# Generated by FakeRAM 2.0
VERSION 5.7 ;
BUSBITCHARS "[]" ;
PROPERTYDEFINITIONS
  MACRO width INTEGER ;
  MACRO depth INTEGER ;
  MACRO banks INTEGER ;
END PROPERTYDEFINITIONS
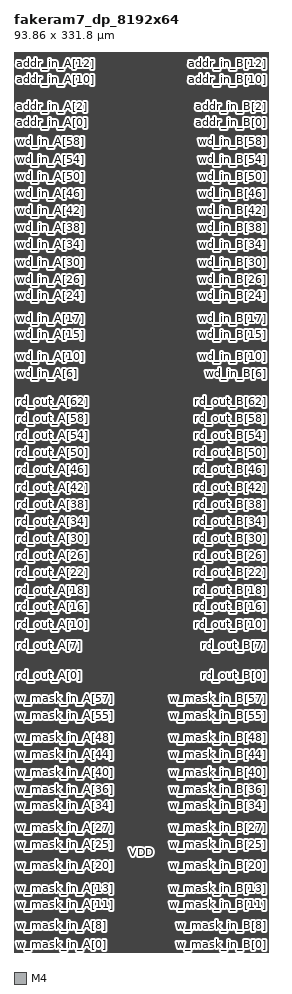
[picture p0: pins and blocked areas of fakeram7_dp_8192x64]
MACRO fakeram7_dp_8192x64
  PROPERTY width 64 ;
  PROPERTY depth 8192 ;
  PROPERTY banks 8 ;
  FOREIGN fakeram7_dp_8192x64 0 0 ;
  SYMMETRY X Y ;
  SIZE 93.860 BY 331.800 ;
  CLASS BLOCK ;
  PIN w_mask_in_A[0]
    DIRECTION INPUT ;
    USE SIGNAL ;
    SHAPE ABUTMENT ;
    PORT
      LAYER M4 ;
      RECT 0.000 0.048 0.024 0.072 ;
    END
  END w_mask_in_A[0]
  PIN w_mask_in_B[0]
    DIRECTION INPUT ;
    USE SIGNAL ;
    SHAPE ABUTMENT ;
    PORT
      LAYER M4 ;
      RECT 93.836 0.048 93.860 0.072 ;
    END
  END w_mask_in_B[0]
  PIN w_mask_in_A[1]
    DIRECTION INPUT ;
    USE SIGNAL ;
    SHAPE ABUTMENT ;
    PORT
      LAYER M4 ;
      RECT 0.000 1.632 0.024 1.656 ;
    END
  END w_mask_in_A[1]
  PIN w_mask_in_B[1]
    DIRECTION INPUT ;
    USE SIGNAL ;
    SHAPE ABUTMENT ;
    PORT
      LAYER M4 ;
      RECT 93.836 1.632 93.860 1.656 ;
    END
  END w_mask_in_B[1]
  PIN w_mask_in_A[2]
    DIRECTION INPUT ;
    USE SIGNAL ;
    SHAPE ABUTMENT ;
    PORT
      LAYER M4 ;
      RECT 0.000 3.216 0.024 3.240 ;
    END
  END w_mask_in_A[2]
  PIN w_mask_in_B[2]
    DIRECTION INPUT ;
    USE SIGNAL ;
    SHAPE ABUTMENT ;
    PORT
      LAYER M4 ;
      RECT 93.836 3.216 93.860 3.240 ;
    END
  END w_mask_in_B[2]
  PIN w_mask_in_A[3]
    DIRECTION INPUT ;
    USE SIGNAL ;
    SHAPE ABUTMENT ;
    PORT
      LAYER M4 ;
      RECT 0.000 4.800 0.024 4.824 ;
    END
  END w_mask_in_A[3]
  PIN w_mask_in_B[3]
    DIRECTION INPUT ;
    USE SIGNAL ;
    SHAPE ABUTMENT ;
    PORT
      LAYER M4 ;
      RECT 93.836 4.800 93.860 4.824 ;
    END
  END w_mask_in_B[3]
  PIN w_mask_in_A[4]
    DIRECTION INPUT ;
    USE SIGNAL ;
    SHAPE ABUTMENT ;
    PORT
      LAYER M4 ;
      RECT 0.000 6.384 0.024 6.408 ;
    END
  END w_mask_in_A[4]
  PIN w_mask_in_B[4]
    DIRECTION INPUT ;
    USE SIGNAL ;
    SHAPE ABUTMENT ;
    PORT
      LAYER M4 ;
      RECT 93.836 6.384 93.860 6.408 ;
    END
  END w_mask_in_B[4]
  PIN w_mask_in_A[5]
    DIRECTION INPUT ;
    USE SIGNAL ;
    SHAPE ABUTMENT ;
    PORT
      LAYER M4 ;
      RECT 0.000 7.968 0.024 7.992 ;
    END
  END w_mask_in_A[5]
  PIN w_mask_in_B[5]
    DIRECTION INPUT ;
    USE SIGNAL ;
    SHAPE ABUTMENT ;
    PORT
      LAYER M4 ;
      RECT 93.836 7.968 93.860 7.992 ;
    END
  END w_mask_in_B[5]
  PIN w_mask_in_A[6]
    DIRECTION INPUT ;
    USE SIGNAL ;
    SHAPE ABUTMENT ;
    PORT
      LAYER M4 ;
      RECT 0.000 9.552 0.024 9.576 ;
    END
  END w_mask_in_A[6]
  PIN w_mask_in_B[6]
    DIRECTION INPUT ;
    USE SIGNAL ;
    SHAPE ABUTMENT ;
    PORT
      LAYER M4 ;
      RECT 93.836 9.552 93.860 9.576 ;
    END
  END w_mask_in_B[6]
  PIN w_mask_in_A[7]
    DIRECTION INPUT ;
    USE SIGNAL ;
    SHAPE ABUTMENT ;
    PORT
      LAYER M4 ;
      RECT 0.000 11.136 0.024 11.160 ;
    END
  END w_mask_in_A[7]
  PIN w_mask_in_B[7]
    DIRECTION INPUT ;
    USE SIGNAL ;
    SHAPE ABUTMENT ;
    PORT
      LAYER M4 ;
      RECT 93.836 11.136 93.860 11.160 ;
    END
  END w_mask_in_B[7]
  PIN w_mask_in_A[8]
    DIRECTION INPUT ;
    USE SIGNAL ;
    SHAPE ABUTMENT ;
    PORT
      LAYER M4 ;
      RECT 0.000 12.720 0.024 12.744 ;
    END
  END w_mask_in_A[8]
  PIN w_mask_in_B[8]
    DIRECTION INPUT ;
    USE SIGNAL ;
    SHAPE ABUTMENT ;
    PORT
      LAYER M4 ;
      RECT 93.836 12.720 93.860 12.744 ;
    END
  END w_mask_in_B[8]
  PIN w_mask_in_A[9]
    DIRECTION INPUT ;
    USE SIGNAL ;
    SHAPE ABUTMENT ;
    PORT
      LAYER M4 ;
      RECT 0.000 14.304 0.024 14.328 ;
    END
  END w_mask_in_A[9]
  PIN w_mask_in_B[9]
    DIRECTION INPUT ;
    USE SIGNAL ;
    SHAPE ABUTMENT ;
    PORT
      LAYER M4 ;
      RECT 93.836 14.304 93.860 14.328 ;
    END
  END w_mask_in_B[9]
  PIN w_mask_in_A[10]
    DIRECTION INPUT ;
    USE SIGNAL ;
    SHAPE ABUTMENT ;
    PORT
      LAYER M4 ;
      RECT 0.000 15.888 0.024 15.912 ;
    END
  END w_mask_in_A[10]
  PIN w_mask_in_B[10]
    DIRECTION INPUT ;
    USE SIGNAL ;
    SHAPE ABUTMENT ;
    PORT
      LAYER M4 ;
      RECT 93.836 15.888 93.860 15.912 ;
    END
  END w_mask_in_B[10]
  PIN w_mask_in_A[11]
    DIRECTION INPUT ;
    USE SIGNAL ;
    SHAPE ABUTMENT ;
    PORT
      LAYER M4 ;
      RECT 0.000 17.472 0.024 17.496 ;
    END
  END w_mask_in_A[11]
  PIN w_mask_in_B[11]
    DIRECTION INPUT ;
    USE SIGNAL ;
    SHAPE ABUTMENT ;
    PORT
      LAYER M4 ;
      RECT 93.836 17.472 93.860 17.496 ;
    END
  END w_mask_in_B[11]
  PIN w_mask_in_A[12]
    DIRECTION INPUT ;
    USE SIGNAL ;
    SHAPE ABUTMENT ;
    PORT
      LAYER M4 ;
      RECT 0.000 19.056 0.024 19.080 ;
    END
  END w_mask_in_A[12]
  PIN w_mask_in_B[12]
    DIRECTION INPUT ;
    USE SIGNAL ;
    SHAPE ABUTMENT ;
    PORT
      LAYER M4 ;
      RECT 93.836 19.056 93.860 19.080 ;
    END
  END w_mask_in_B[12]
  PIN w_mask_in_A[13]
    DIRECTION INPUT ;
    USE SIGNAL ;
    SHAPE ABUTMENT ;
    PORT
      LAYER M4 ;
      RECT 0.000 20.640 0.024 20.664 ;
    END
  END w_mask_in_A[13]
  PIN w_mask_in_B[13]
    DIRECTION INPUT ;
    USE SIGNAL ;
    SHAPE ABUTMENT ;
    PORT
      LAYER M4 ;
      RECT 93.836 20.640 93.860 20.664 ;
    END
  END w_mask_in_B[13]
  PIN w_mask_in_A[14]
    DIRECTION INPUT ;
    USE SIGNAL ;
    SHAPE ABUTMENT ;
    PORT
      LAYER M4 ;
      RECT 0.000 22.224 0.024 22.248 ;
    END
  END w_mask_in_A[14]
  PIN w_mask_in_B[14]
    DIRECTION INPUT ;
    USE SIGNAL ;
    SHAPE ABUTMENT ;
    PORT
      LAYER M4 ;
      RECT 93.836 22.224 93.860 22.248 ;
    END
  END w_mask_in_B[14]
  PIN w_mask_in_A[15]
    DIRECTION INPUT ;
    USE SIGNAL ;
    SHAPE ABUTMENT ;
    PORT
      LAYER M4 ;
      RECT 0.000 23.808 0.024 23.832 ;
    END
  END w_mask_in_A[15]
  PIN w_mask_in_B[15]
    DIRECTION INPUT ;
    USE SIGNAL ;
    SHAPE ABUTMENT ;
    PORT
      LAYER M4 ;
      RECT 93.836 23.808 93.860 23.832 ;
    END
  END w_mask_in_B[15]
  PIN w_mask_in_A[16]
    DIRECTION INPUT ;
    USE SIGNAL ;
    SHAPE ABUTMENT ;
    PORT
      LAYER M4 ;
      RECT 0.000 25.392 0.024 25.416 ;
    END
  END w_mask_in_A[16]
  PIN w_mask_in_B[16]
    DIRECTION INPUT ;
    USE SIGNAL ;
    SHAPE ABUTMENT ;
    PORT
      LAYER M4 ;
      RECT 93.836 25.392 93.860 25.416 ;
    END
  END w_mask_in_B[16]
  PIN w_mask_in_A[17]
    DIRECTION INPUT ;
    USE SIGNAL ;
    SHAPE ABUTMENT ;
    PORT
      LAYER M4 ;
      RECT 0.000 26.976 0.024 27.000 ;
    END
  END w_mask_in_A[17]
  PIN w_mask_in_B[17]
    DIRECTION INPUT ;
    USE SIGNAL ;
    SHAPE ABUTMENT ;
    PORT
      LAYER M4 ;
      RECT 93.836 26.976 93.860 27.000 ;
    END
  END w_mask_in_B[17]
  PIN w_mask_in_A[18]
    DIRECTION INPUT ;
    USE SIGNAL ;
    SHAPE ABUTMENT ;
    PORT
      LAYER M4 ;
      RECT 0.000 28.560 0.024 28.584 ;
    END
  END w_mask_in_A[18]
  PIN w_mask_in_B[18]
    DIRECTION INPUT ;
    USE SIGNAL ;
    SHAPE ABUTMENT ;
    PORT
      LAYER M4 ;
      RECT 93.836 28.560 93.860 28.584 ;
    END
  END w_mask_in_B[18]
  PIN w_mask_in_A[19]
    DIRECTION INPUT ;
    USE SIGNAL ;
    SHAPE ABUTMENT ;
    PORT
      LAYER M4 ;
      RECT 0.000 30.144 0.024 30.168 ;
    END
  END w_mask_in_A[19]
  PIN w_mask_in_B[19]
    DIRECTION INPUT ;
    USE SIGNAL ;
    SHAPE ABUTMENT ;
    PORT
      LAYER M4 ;
      RECT 93.836 30.144 93.860 30.168 ;
    END
  END w_mask_in_B[19]
  PIN w_mask_in_A[20]
    DIRECTION INPUT ;
    USE SIGNAL ;
    SHAPE ABUTMENT ;
    PORT
      LAYER M4 ;
      RECT 0.000 31.728 0.024 31.752 ;
    END
  END w_mask_in_A[20]
  PIN w_mask_in_B[20]
    DIRECTION INPUT ;
    USE SIGNAL ;
    SHAPE ABUTMENT ;
    PORT
      LAYER M4 ;
      RECT 93.836 31.728 93.860 31.752 ;
    END
  END w_mask_in_B[20]
  PIN w_mask_in_A[21]
    DIRECTION INPUT ;
    USE SIGNAL ;
    SHAPE ABUTMENT ;
    PORT
      LAYER M4 ;
      RECT 0.000 33.312 0.024 33.336 ;
    END
  END w_mask_in_A[21]
  PIN w_mask_in_B[21]
    DIRECTION INPUT ;
    USE SIGNAL ;
    SHAPE ABUTMENT ;
    PORT
      LAYER M4 ;
      RECT 93.836 33.312 93.860 33.336 ;
    END
  END w_mask_in_B[21]
  PIN w_mask_in_A[22]
    DIRECTION INPUT ;
    USE SIGNAL ;
    SHAPE ABUTMENT ;
    PORT
      LAYER M4 ;
      RECT 0.000 34.896 0.024 34.920 ;
    END
  END w_mask_in_A[22]
  PIN w_mask_in_B[22]
    DIRECTION INPUT ;
    USE SIGNAL ;
    SHAPE ABUTMENT ;
    PORT
      LAYER M4 ;
      RECT 93.836 34.896 93.860 34.920 ;
    END
  END w_mask_in_B[22]
  PIN w_mask_in_A[23]
    DIRECTION INPUT ;
    USE SIGNAL ;
    SHAPE ABUTMENT ;
    PORT
      LAYER M4 ;
      RECT 0.000 36.480 0.024 36.504 ;
    END
  END w_mask_in_A[23]
  PIN w_mask_in_B[23]
    DIRECTION INPUT ;
    USE SIGNAL ;
    SHAPE ABUTMENT ;
    PORT
      LAYER M4 ;
      RECT 93.836 36.480 93.860 36.504 ;
    END
  END w_mask_in_B[23]
  PIN w_mask_in_A[24]
    DIRECTION INPUT ;
    USE SIGNAL ;
    SHAPE ABUTMENT ;
    PORT
      LAYER M4 ;
      RECT 0.000 38.064 0.024 38.088 ;
    END
  END w_mask_in_A[24]
  PIN w_mask_in_B[24]
    DIRECTION INPUT ;
    USE SIGNAL ;
    SHAPE ABUTMENT ;
    PORT
      LAYER M4 ;
      RECT 93.836 38.064 93.860 38.088 ;
    END
  END w_mask_in_B[24]
  PIN w_mask_in_A[25]
    DIRECTION INPUT ;
    USE SIGNAL ;
    SHAPE ABUTMENT ;
    PORT
      LAYER M4 ;
      RECT 0.000 39.648 0.024 39.672 ;
    END
  END w_mask_in_A[25]
  PIN w_mask_in_B[25]
    DIRECTION INPUT ;
    USE SIGNAL ;
    SHAPE ABUTMENT ;
    PORT
      LAYER M4 ;
      RECT 93.836 39.648 93.860 39.672 ;
    END
  END w_mask_in_B[25]
  PIN w_mask_in_A[26]
    DIRECTION INPUT ;
    USE SIGNAL ;
    SHAPE ABUTMENT ;
    PORT
      LAYER M4 ;
      RECT 0.000 41.232 0.024 41.256 ;
    END
  END w_mask_in_A[26]
  PIN w_mask_in_B[26]
    DIRECTION INPUT ;
    USE SIGNAL ;
    SHAPE ABUTMENT ;
    PORT
      LAYER M4 ;
      RECT 93.836 41.232 93.860 41.256 ;
    END
  END w_mask_in_B[26]
  PIN w_mask_in_A[27]
    DIRECTION INPUT ;
    USE SIGNAL ;
    SHAPE ABUTMENT ;
    PORT
      LAYER M4 ;
      RECT 0.000 42.816 0.024 42.840 ;
    END
  END w_mask_in_A[27]
  PIN w_mask_in_B[27]
    DIRECTION INPUT ;
    USE SIGNAL ;
    SHAPE ABUTMENT ;
    PORT
      LAYER M4 ;
      RECT 93.836 42.816 93.860 42.840 ;
    END
  END w_mask_in_B[27]
  PIN w_mask_in_A[28]
    DIRECTION INPUT ;
    USE SIGNAL ;
    SHAPE ABUTMENT ;
    PORT
      LAYER M4 ;
      RECT 0.000 44.400 0.024 44.424 ;
    END
  END w_mask_in_A[28]
  PIN w_mask_in_B[28]
    DIRECTION INPUT ;
    USE SIGNAL ;
    SHAPE ABUTMENT ;
    PORT
      LAYER M4 ;
      RECT 93.836 44.400 93.860 44.424 ;
    END
  END w_mask_in_B[28]
  PIN w_mask_in_A[29]
    DIRECTION INPUT ;
    USE SIGNAL ;
    SHAPE ABUTMENT ;
    PORT
      LAYER M4 ;
      RECT 0.000 45.984 0.024 46.008 ;
    END
  END w_mask_in_A[29]
  PIN w_mask_in_B[29]
    DIRECTION INPUT ;
    USE SIGNAL ;
    SHAPE ABUTMENT ;
    PORT
      LAYER M4 ;
      RECT 93.836 45.984 93.860 46.008 ;
    END
  END w_mask_in_B[29]
  PIN w_mask_in_A[30]
    DIRECTION INPUT ;
    USE SIGNAL ;
    SHAPE ABUTMENT ;
    PORT
      LAYER M4 ;
      RECT 0.000 47.568 0.024 47.592 ;
    END
  END w_mask_in_A[30]
  PIN w_mask_in_B[30]
    DIRECTION INPUT ;
    USE SIGNAL ;
    SHAPE ABUTMENT ;
    PORT
      LAYER M4 ;
      RECT 93.836 47.568 93.860 47.592 ;
    END
  END w_mask_in_B[30]
  PIN w_mask_in_A[31]
    DIRECTION INPUT ;
    USE SIGNAL ;
    SHAPE ABUTMENT ;
    PORT
      LAYER M4 ;
      RECT 0.000 49.152 0.024 49.176 ;
    END
  END w_mask_in_A[31]
  PIN w_mask_in_B[31]
    DIRECTION INPUT ;
    USE SIGNAL ;
    SHAPE ABUTMENT ;
    PORT
      LAYER M4 ;
      RECT 93.836 49.152 93.860 49.176 ;
    END
  END w_mask_in_B[31]
  PIN w_mask_in_A[32]
    DIRECTION INPUT ;
    USE SIGNAL ;
    SHAPE ABUTMENT ;
    PORT
      LAYER M4 ;
      RECT 0.000 50.736 0.024 50.760 ;
    END
  END w_mask_in_A[32]
  PIN w_mask_in_B[32]
    DIRECTION INPUT ;
    USE SIGNAL ;
    SHAPE ABUTMENT ;
    PORT
      LAYER M4 ;
      RECT 93.836 50.736 93.860 50.760 ;
    END
  END w_mask_in_B[32]
  PIN w_mask_in_A[33]
    DIRECTION INPUT ;
    USE SIGNAL ;
    SHAPE ABUTMENT ;
    PORT
      LAYER M4 ;
      RECT 0.000 52.320 0.024 52.344 ;
    END
  END w_mask_in_A[33]
  PIN w_mask_in_B[33]
    DIRECTION INPUT ;
    USE SIGNAL ;
    SHAPE ABUTMENT ;
    PORT
      LAYER M4 ;
      RECT 93.836 52.320 93.860 52.344 ;
    END
  END w_mask_in_B[33]
  PIN w_mask_in_A[34]
    DIRECTION INPUT ;
    USE SIGNAL ;
    SHAPE ABUTMENT ;
    PORT
      LAYER M4 ;
      RECT 0.000 53.904 0.024 53.928 ;
    END
  END w_mask_in_A[34]
  PIN w_mask_in_B[34]
    DIRECTION INPUT ;
    USE SIGNAL ;
    SHAPE ABUTMENT ;
    PORT
      LAYER M4 ;
      RECT 93.836 53.904 93.860 53.928 ;
    END
  END w_mask_in_B[34]
  PIN w_mask_in_A[35]
    DIRECTION INPUT ;
    USE SIGNAL ;
    SHAPE ABUTMENT ;
    PORT
      LAYER M4 ;
      RECT 0.000 55.488 0.024 55.512 ;
    END
  END w_mask_in_A[35]
  PIN w_mask_in_B[35]
    DIRECTION INPUT ;
    USE SIGNAL ;
    SHAPE ABUTMENT ;
    PORT
      LAYER M4 ;
      RECT 93.836 55.488 93.860 55.512 ;
    END
  END w_mask_in_B[35]
  PIN w_mask_in_A[36]
    DIRECTION INPUT ;
    USE SIGNAL ;
    SHAPE ABUTMENT ;
    PORT
      LAYER M4 ;
      RECT 0.000 57.072 0.024 57.096 ;
    END
  END w_mask_in_A[36]
  PIN w_mask_in_B[36]
    DIRECTION INPUT ;
    USE SIGNAL ;
    SHAPE ABUTMENT ;
    PORT
      LAYER M4 ;
      RECT 93.836 57.072 93.860 57.096 ;
    END
  END w_mask_in_B[36]
  PIN w_mask_in_A[37]
    DIRECTION INPUT ;
    USE SIGNAL ;
    SHAPE ABUTMENT ;
    PORT
      LAYER M4 ;
      RECT 0.000 58.656 0.024 58.680 ;
    END
  END w_mask_in_A[37]
  PIN w_mask_in_B[37]
    DIRECTION INPUT ;
    USE SIGNAL ;
    SHAPE ABUTMENT ;
    PORT
      LAYER M4 ;
      RECT 93.836 58.656 93.860 58.680 ;
    END
  END w_mask_in_B[37]
  PIN w_mask_in_A[38]
    DIRECTION INPUT ;
    USE SIGNAL ;
    SHAPE ABUTMENT ;
    PORT
      LAYER M4 ;
      RECT 0.000 60.240 0.024 60.264 ;
    END
  END w_mask_in_A[38]
  PIN w_mask_in_B[38]
    DIRECTION INPUT ;
    USE SIGNAL ;
    SHAPE ABUTMENT ;
    PORT
      LAYER M4 ;
      RECT 93.836 60.240 93.860 60.264 ;
    END
  END w_mask_in_B[38]
  PIN w_mask_in_A[39]
    DIRECTION INPUT ;
    USE SIGNAL ;
    SHAPE ABUTMENT ;
    PORT
      LAYER M4 ;
      RECT 0.000 61.824 0.024 61.848 ;
    END
  END w_mask_in_A[39]
  PIN w_mask_in_B[39]
    DIRECTION INPUT ;
    USE SIGNAL ;
    SHAPE ABUTMENT ;
    PORT
      LAYER M4 ;
      RECT 93.836 61.824 93.860 61.848 ;
    END
  END w_mask_in_B[39]
  PIN w_mask_in_A[40]
    DIRECTION INPUT ;
    USE SIGNAL ;
    SHAPE ABUTMENT ;
    PORT
      LAYER M4 ;
      RECT 0.000 63.408 0.024 63.432 ;
    END
  END w_mask_in_A[40]
  PIN w_mask_in_B[40]
    DIRECTION INPUT ;
    USE SIGNAL ;
    SHAPE ABUTMENT ;
    PORT
      LAYER M4 ;
      RECT 93.836 63.408 93.860 63.432 ;
    END
  END w_mask_in_B[40]
  PIN w_mask_in_A[41]
    DIRECTION INPUT ;
    USE SIGNAL ;
    SHAPE ABUTMENT ;
    PORT
      LAYER M4 ;
      RECT 0.000 64.992 0.024 65.016 ;
    END
  END w_mask_in_A[41]
  PIN w_mask_in_B[41]
    DIRECTION INPUT ;
    USE SIGNAL ;
    SHAPE ABUTMENT ;
    PORT
      LAYER M4 ;
      RECT 93.836 64.992 93.860 65.016 ;
    END
  END w_mask_in_B[41]
  PIN w_mask_in_A[42]
    DIRECTION INPUT ;
    USE SIGNAL ;
    SHAPE ABUTMENT ;
    PORT
      LAYER M4 ;
      RECT 0.000 66.576 0.024 66.600 ;
    END
  END w_mask_in_A[42]
  PIN w_mask_in_B[42]
    DIRECTION INPUT ;
    USE SIGNAL ;
    SHAPE ABUTMENT ;
    PORT
      LAYER M4 ;
      RECT 93.836 66.576 93.860 66.600 ;
    END
  END w_mask_in_B[42]
  PIN w_mask_in_A[43]
    DIRECTION INPUT ;
    USE SIGNAL ;
    SHAPE ABUTMENT ;
    PORT
      LAYER M4 ;
      RECT 0.000 68.160 0.024 68.184 ;
    END
  END w_mask_in_A[43]
  PIN w_mask_in_B[43]
    DIRECTION INPUT ;
    USE SIGNAL ;
    SHAPE ABUTMENT ;
    PORT
      LAYER M4 ;
      RECT 93.836 68.160 93.860 68.184 ;
    END
  END w_mask_in_B[43]
  PIN w_mask_in_A[44]
    DIRECTION INPUT ;
    USE SIGNAL ;
    SHAPE ABUTMENT ;
    PORT
      LAYER M4 ;
      RECT 0.000 69.744 0.024 69.768 ;
    END
  END w_mask_in_A[44]
  PIN w_mask_in_B[44]
    DIRECTION INPUT ;
    USE SIGNAL ;
    SHAPE ABUTMENT ;
    PORT
      LAYER M4 ;
      RECT 93.836 69.744 93.860 69.768 ;
    END
  END w_mask_in_B[44]
  PIN w_mask_in_A[45]
    DIRECTION INPUT ;
    USE SIGNAL ;
    SHAPE ABUTMENT ;
    PORT
      LAYER M4 ;
      RECT 0.000 71.328 0.024 71.352 ;
    END
  END w_mask_in_A[45]
  PIN w_mask_in_B[45]
    DIRECTION INPUT ;
    USE SIGNAL ;
    SHAPE ABUTMENT ;
    PORT
      LAYER M4 ;
      RECT 93.836 71.328 93.860 71.352 ;
    END
  END w_mask_in_B[45]
  PIN w_mask_in_A[46]
    DIRECTION INPUT ;
    USE SIGNAL ;
    SHAPE ABUTMENT ;
    PORT
      LAYER M4 ;
      RECT 0.000 72.912 0.024 72.936 ;
    END
  END w_mask_in_A[46]
  PIN w_mask_in_B[46]
    DIRECTION INPUT ;
    USE SIGNAL ;
    SHAPE ABUTMENT ;
    PORT
      LAYER M4 ;
      RECT 93.836 72.912 93.860 72.936 ;
    END
  END w_mask_in_B[46]
  PIN w_mask_in_A[47]
    DIRECTION INPUT ;
    USE SIGNAL ;
    SHAPE ABUTMENT ;
    PORT
      LAYER M4 ;
      RECT 0.000 74.496 0.024 74.520 ;
    END
  END w_mask_in_A[47]
  PIN w_mask_in_B[47]
    DIRECTION INPUT ;
    USE SIGNAL ;
    SHAPE ABUTMENT ;
    PORT
      LAYER M4 ;
      RECT 93.836 74.496 93.860 74.520 ;
    END
  END w_mask_in_B[47]
  PIN w_mask_in_A[48]
    DIRECTION INPUT ;
    USE SIGNAL ;
    SHAPE ABUTMENT ;
    PORT
      LAYER M4 ;
      RECT 0.000 76.080 0.024 76.104 ;
    END
  END w_mask_in_A[48]
  PIN w_mask_in_B[48]
    DIRECTION INPUT ;
    USE SIGNAL ;
    SHAPE ABUTMENT ;
    PORT
      LAYER M4 ;
      RECT 93.836 76.080 93.860 76.104 ;
    END
  END w_mask_in_B[48]
  PIN w_mask_in_A[49]
    DIRECTION INPUT ;
    USE SIGNAL ;
    SHAPE ABUTMENT ;
    PORT
      LAYER M4 ;
      RECT 0.000 77.664 0.024 77.688 ;
    END
  END w_mask_in_A[49]
  PIN w_mask_in_B[49]
    DIRECTION INPUT ;
    USE SIGNAL ;
    SHAPE ABUTMENT ;
    PORT
      LAYER M4 ;
      RECT 93.836 77.664 93.860 77.688 ;
    END
  END w_mask_in_B[49]
  PIN w_mask_in_A[50]
    DIRECTION INPUT ;
    USE SIGNAL ;
    SHAPE ABUTMENT ;
    PORT
      LAYER M4 ;
      RECT 0.000 79.248 0.024 79.272 ;
    END
  END w_mask_in_A[50]
  PIN w_mask_in_B[50]
    DIRECTION INPUT ;
    USE SIGNAL ;
    SHAPE ABUTMENT ;
    PORT
      LAYER M4 ;
      RECT 93.836 79.248 93.860 79.272 ;
    END
  END w_mask_in_B[50]
  PIN w_mask_in_A[51]
    DIRECTION INPUT ;
    USE SIGNAL ;
    SHAPE ABUTMENT ;
    PORT
      LAYER M4 ;
      RECT 0.000 80.832 0.024 80.856 ;
    END
  END w_mask_in_A[51]
  PIN w_mask_in_B[51]
    DIRECTION INPUT ;
    USE SIGNAL ;
    SHAPE ABUTMENT ;
    PORT
      LAYER M4 ;
      RECT 93.836 80.832 93.860 80.856 ;
    END
  END w_mask_in_B[51]
  PIN w_mask_in_A[52]
    DIRECTION INPUT ;
    USE SIGNAL ;
    SHAPE ABUTMENT ;
    PORT
      LAYER M4 ;
      RECT 0.000 82.416 0.024 82.440 ;
    END
  END w_mask_in_A[52]
  PIN w_mask_in_B[52]
    DIRECTION INPUT ;
    USE SIGNAL ;
    SHAPE ABUTMENT ;
    PORT
      LAYER M4 ;
      RECT 93.836 82.416 93.860 82.440 ;
    END
  END w_mask_in_B[52]
  PIN w_mask_in_A[53]
    DIRECTION INPUT ;
    USE SIGNAL ;
    SHAPE ABUTMENT ;
    PORT
      LAYER M4 ;
      RECT 0.000 84.000 0.024 84.024 ;
    END
  END w_mask_in_A[53]
  PIN w_mask_in_B[53]
    DIRECTION INPUT ;
    USE SIGNAL ;
    SHAPE ABUTMENT ;
    PORT
      LAYER M4 ;
      RECT 93.836 84.000 93.860 84.024 ;
    END
  END w_mask_in_B[53]
  PIN w_mask_in_A[54]
    DIRECTION INPUT ;
    USE SIGNAL ;
    SHAPE ABUTMENT ;
    PORT
      LAYER M4 ;
      RECT 0.000 85.584 0.024 85.608 ;
    END
  END w_mask_in_A[54]
  PIN w_mask_in_B[54]
    DIRECTION INPUT ;
    USE SIGNAL ;
    SHAPE ABUTMENT ;
    PORT
      LAYER M4 ;
      RECT 93.836 85.584 93.860 85.608 ;
    END
  END w_mask_in_B[54]
  PIN w_mask_in_A[55]
    DIRECTION INPUT ;
    USE SIGNAL ;
    SHAPE ABUTMENT ;
    PORT
      LAYER M4 ;
      RECT 0.000 87.168 0.024 87.192 ;
    END
  END w_mask_in_A[55]
  PIN w_mask_in_B[55]
    DIRECTION INPUT ;
    USE SIGNAL ;
    SHAPE ABUTMENT ;
    PORT
      LAYER M4 ;
      RECT 93.836 87.168 93.860 87.192 ;
    END
  END w_mask_in_B[55]
  PIN w_mask_in_A[56]
    DIRECTION INPUT ;
    USE SIGNAL ;
    SHAPE ABUTMENT ;
    PORT
      LAYER M4 ;
      RECT 0.000 88.752 0.024 88.776 ;
    END
  END w_mask_in_A[56]
  PIN w_mask_in_B[56]
    DIRECTION INPUT ;
    USE SIGNAL ;
    SHAPE ABUTMENT ;
    PORT
      LAYER M4 ;
      RECT 93.836 88.752 93.860 88.776 ;
    END
  END w_mask_in_B[56]
  PIN w_mask_in_A[57]
    DIRECTION INPUT ;
    USE SIGNAL ;
    SHAPE ABUTMENT ;
    PORT
      LAYER M4 ;
      RECT 0.000 90.336 0.024 90.360 ;
    END
  END w_mask_in_A[57]
  PIN w_mask_in_B[57]
    DIRECTION INPUT ;
    USE SIGNAL ;
    SHAPE ABUTMENT ;
    PORT
      LAYER M4 ;
      RECT 93.836 90.336 93.860 90.360 ;
    END
  END w_mask_in_B[57]
  PIN w_mask_in_A[58]
    DIRECTION INPUT ;
    USE SIGNAL ;
    SHAPE ABUTMENT ;
    PORT
      LAYER M4 ;
      RECT 0.000 91.920 0.024 91.944 ;
    END
  END w_mask_in_A[58]
  PIN w_mask_in_B[58]
    DIRECTION INPUT ;
    USE SIGNAL ;
    SHAPE ABUTMENT ;
    PORT
      LAYER M4 ;
      RECT 93.836 91.920 93.860 91.944 ;
    END
  END w_mask_in_B[58]
  PIN w_mask_in_A[59]
    DIRECTION INPUT ;
    USE SIGNAL ;
    SHAPE ABUTMENT ;
    PORT
      LAYER M4 ;
      RECT 0.000 93.504 0.024 93.528 ;
    END
  END w_mask_in_A[59]
  PIN w_mask_in_B[59]
    DIRECTION INPUT ;
    USE SIGNAL ;
    SHAPE ABUTMENT ;
    PORT
      LAYER M4 ;
      RECT 93.836 93.504 93.860 93.528 ;
    END
  END w_mask_in_B[59]
  PIN w_mask_in_A[60]
    DIRECTION INPUT ;
    USE SIGNAL ;
    SHAPE ABUTMENT ;
    PORT
      LAYER M4 ;
      RECT 0.000 95.088 0.024 95.112 ;
    END
  END w_mask_in_A[60]
  PIN w_mask_in_B[60]
    DIRECTION INPUT ;
    USE SIGNAL ;
    SHAPE ABUTMENT ;
    PORT
      LAYER M4 ;
      RECT 93.836 95.088 93.860 95.112 ;
    END
  END w_mask_in_B[60]
  PIN w_mask_in_A[61]
    DIRECTION INPUT ;
    USE SIGNAL ;
    SHAPE ABUTMENT ;
    PORT
      LAYER M4 ;
      RECT 0.000 96.672 0.024 96.696 ;
    END
  END w_mask_in_A[61]
  PIN w_mask_in_B[61]
    DIRECTION INPUT ;
    USE SIGNAL ;
    SHAPE ABUTMENT ;
    PORT
      LAYER M4 ;
      RECT 93.836 96.672 93.860 96.696 ;
    END
  END w_mask_in_B[61]
  PIN w_mask_in_A[62]
    DIRECTION INPUT ;
    USE SIGNAL ;
    SHAPE ABUTMENT ;
    PORT
      LAYER M4 ;
      RECT 0.000 98.256 0.024 98.280 ;
    END
  END w_mask_in_A[62]
  PIN w_mask_in_B[62]
    DIRECTION INPUT ;
    USE SIGNAL ;
    SHAPE ABUTMENT ;
    PORT
      LAYER M4 ;
      RECT 93.836 98.256 93.860 98.280 ;
    END
  END w_mask_in_B[62]
  PIN w_mask_in_A[63]
    DIRECTION INPUT ;
    USE SIGNAL ;
    SHAPE ABUTMENT ;
    PORT
      LAYER M4 ;
      RECT 0.000 99.840 0.024 99.864 ;
    END
  END w_mask_in_A[63]
  PIN w_mask_in_B[63]
    DIRECTION INPUT ;
    USE SIGNAL ;
    SHAPE ABUTMENT ;
    PORT
      LAYER M4 ;
      RECT 93.836 99.840 93.860 99.864 ;
    END
  END w_mask_in_B[63]
  PIN rd_out_A[0]
    DIRECTION OUTPUT ;
    USE SIGNAL ;
    SHAPE ABUTMENT ;
    PORT
      LAYER M4 ;
      RECT 0.000 101.952 0.024 101.976 ;
    END
  END rd_out_A[0]
  PIN rd_out_B[0]
    DIRECTION OUTPUT ;
    USE SIGNAL ;
    SHAPE ABUTMENT ;
    PORT
      LAYER M4 ;
      RECT 93.836 101.952 93.860 101.976 ;
    END
  END rd_out_B[0]
  PIN rd_out_A[1]
    DIRECTION OUTPUT ;
    USE SIGNAL ;
    SHAPE ABUTMENT ;
    PORT
      LAYER M4 ;
      RECT 0.000 103.536 0.024 103.560 ;
    END
  END rd_out_A[1]
  PIN rd_out_B[1]
    DIRECTION OUTPUT ;
    USE SIGNAL ;
    SHAPE ABUTMENT ;
    PORT
      LAYER M4 ;
      RECT 93.836 103.536 93.860 103.560 ;
    END
  END rd_out_B[1]
  PIN rd_out_A[2]
    DIRECTION OUTPUT ;
    USE SIGNAL ;
    SHAPE ABUTMENT ;
    PORT
      LAYER M4 ;
      RECT 0.000 105.120 0.024 105.144 ;
    END
  END rd_out_A[2]
  PIN rd_out_B[2]
    DIRECTION OUTPUT ;
    USE SIGNAL ;
    SHAPE ABUTMENT ;
    PORT
      LAYER M4 ;
      RECT 93.836 105.120 93.860 105.144 ;
    END
  END rd_out_B[2]
  PIN rd_out_A[3]
    DIRECTION OUTPUT ;
    USE SIGNAL ;
    SHAPE ABUTMENT ;
    PORT
      LAYER M4 ;
      RECT 0.000 106.704 0.024 106.728 ;
    END
  END rd_out_A[3]
  PIN rd_out_B[3]
    DIRECTION OUTPUT ;
    USE SIGNAL ;
    SHAPE ABUTMENT ;
    PORT
      LAYER M4 ;
      RECT 93.836 106.704 93.860 106.728 ;
    END
  END rd_out_B[3]
  PIN rd_out_A[4]
    DIRECTION OUTPUT ;
    USE SIGNAL ;
    SHAPE ABUTMENT ;
    PORT
      LAYER M4 ;
      RECT 0.000 108.288 0.024 108.312 ;
    END
  END rd_out_A[4]
  PIN rd_out_B[4]
    DIRECTION OUTPUT ;
    USE SIGNAL ;
    SHAPE ABUTMENT ;
    PORT
      LAYER M4 ;
      RECT 93.836 108.288 93.860 108.312 ;
    END
  END rd_out_B[4]
  PIN rd_out_A[5]
    DIRECTION OUTPUT ;
    USE SIGNAL ;
    SHAPE ABUTMENT ;
    PORT
      LAYER M4 ;
      RECT 0.000 109.872 0.024 109.896 ;
    END
  END rd_out_A[5]
  PIN rd_out_B[5]
    DIRECTION OUTPUT ;
    USE SIGNAL ;
    SHAPE ABUTMENT ;
    PORT
      LAYER M4 ;
      RECT 93.836 109.872 93.860 109.896 ;
    END
  END rd_out_B[5]
  PIN rd_out_A[6]
    DIRECTION OUTPUT ;
    USE SIGNAL ;
    SHAPE ABUTMENT ;
    PORT
      LAYER M4 ;
      RECT 0.000 111.456 0.024 111.480 ;
    END
  END rd_out_A[6]
  PIN rd_out_B[6]
    DIRECTION OUTPUT ;
    USE SIGNAL ;
    SHAPE ABUTMENT ;
    PORT
      LAYER M4 ;
      RECT 93.836 111.456 93.860 111.480 ;
    END
  END rd_out_B[6]
  PIN rd_out_A[7]
    DIRECTION OUTPUT ;
    USE SIGNAL ;
    SHAPE ABUTMENT ;
    PORT
      LAYER M4 ;
      RECT 0.000 113.040 0.024 113.064 ;
    END
  END rd_out_A[7]
  PIN rd_out_B[7]
    DIRECTION OUTPUT ;
    USE SIGNAL ;
    SHAPE ABUTMENT ;
    PORT
      LAYER M4 ;
      RECT 93.836 113.040 93.860 113.064 ;
    END
  END rd_out_B[7]
  PIN rd_out_A[8]
    DIRECTION OUTPUT ;
    USE SIGNAL ;
    SHAPE ABUTMENT ;
    PORT
      LAYER M4 ;
      RECT 0.000 114.624 0.024 114.648 ;
    END
  END rd_out_A[8]
  PIN rd_out_B[8]
    DIRECTION OUTPUT ;
    USE SIGNAL ;
    SHAPE ABUTMENT ;
    PORT
      LAYER M4 ;
      RECT 93.836 114.624 93.860 114.648 ;
    END
  END rd_out_B[8]
  PIN rd_out_A[9]
    DIRECTION OUTPUT ;
    USE SIGNAL ;
    SHAPE ABUTMENT ;
    PORT
      LAYER M4 ;
      RECT 0.000 116.208 0.024 116.232 ;
    END
  END rd_out_A[9]
  PIN rd_out_B[9]
    DIRECTION OUTPUT ;
    USE SIGNAL ;
    SHAPE ABUTMENT ;
    PORT
      LAYER M4 ;
      RECT 93.836 116.208 93.860 116.232 ;
    END
  END rd_out_B[9]
  PIN rd_out_A[10]
    DIRECTION OUTPUT ;
    USE SIGNAL ;
    SHAPE ABUTMENT ;
    PORT
      LAYER M4 ;
      RECT 0.000 117.792 0.024 117.816 ;
    END
  END rd_out_A[10]
  PIN rd_out_B[10]
    DIRECTION OUTPUT ;
    USE SIGNAL ;
    SHAPE ABUTMENT ;
    PORT
      LAYER M4 ;
      RECT 93.836 117.792 93.860 117.816 ;
    END
  END rd_out_B[10]
  PIN rd_out_A[11]
    DIRECTION OUTPUT ;
    USE SIGNAL ;
    SHAPE ABUTMENT ;
    PORT
      LAYER M4 ;
      RECT 0.000 119.376 0.024 119.400 ;
    END
  END rd_out_A[11]
  PIN rd_out_B[11]
    DIRECTION OUTPUT ;
    USE SIGNAL ;
    SHAPE ABUTMENT ;
    PORT
      LAYER M4 ;
      RECT 93.836 119.376 93.860 119.400 ;
    END
  END rd_out_B[11]
  PIN rd_out_A[12]
    DIRECTION OUTPUT ;
    USE SIGNAL ;
    SHAPE ABUTMENT ;
    PORT
      LAYER M4 ;
      RECT 0.000 120.960 0.024 120.984 ;
    END
  END rd_out_A[12]
  PIN rd_out_B[12]
    DIRECTION OUTPUT ;
    USE SIGNAL ;
    SHAPE ABUTMENT ;
    PORT
      LAYER M4 ;
      RECT 93.836 120.960 93.860 120.984 ;
    END
  END rd_out_B[12]
  PIN rd_out_A[13]
    DIRECTION OUTPUT ;
    USE SIGNAL ;
    SHAPE ABUTMENT ;
    PORT
      LAYER M4 ;
      RECT 0.000 122.544 0.024 122.568 ;
    END
  END rd_out_A[13]
  PIN rd_out_B[13]
    DIRECTION OUTPUT ;
    USE SIGNAL ;
    SHAPE ABUTMENT ;
    PORT
      LAYER M4 ;
      RECT 93.836 122.544 93.860 122.568 ;
    END
  END rd_out_B[13]
  PIN rd_out_A[14]
    DIRECTION OUTPUT ;
    USE SIGNAL ;
    SHAPE ABUTMENT ;
    PORT
      LAYER M4 ;
      RECT 0.000 124.128 0.024 124.152 ;
    END
  END rd_out_A[14]
  PIN rd_out_B[14]
    DIRECTION OUTPUT ;
    USE SIGNAL ;
    SHAPE ABUTMENT ;
    PORT
      LAYER M4 ;
      RECT 93.836 124.128 93.860 124.152 ;
    END
  END rd_out_B[14]
  PIN rd_out_A[15]
    DIRECTION OUTPUT ;
    USE SIGNAL ;
    SHAPE ABUTMENT ;
    PORT
      LAYER M4 ;
      RECT 0.000 125.712 0.024 125.736 ;
    END
  END rd_out_A[15]
  PIN rd_out_B[15]
    DIRECTION OUTPUT ;
    USE SIGNAL ;
    SHAPE ABUTMENT ;
    PORT
      LAYER M4 ;
      RECT 93.836 125.712 93.860 125.736 ;
    END
  END rd_out_B[15]
  PIN rd_out_A[16]
    DIRECTION OUTPUT ;
    USE SIGNAL ;
    SHAPE ABUTMENT ;
    PORT
      LAYER M4 ;
      RECT 0.000 127.296 0.024 127.320 ;
    END
  END rd_out_A[16]
  PIN rd_out_B[16]
    DIRECTION OUTPUT ;
    USE SIGNAL ;
    SHAPE ABUTMENT ;
    PORT
      LAYER M4 ;
      RECT 93.836 127.296 93.860 127.320 ;
    END
  END rd_out_B[16]
  PIN rd_out_A[17]
    DIRECTION OUTPUT ;
    USE SIGNAL ;
    SHAPE ABUTMENT ;
    PORT
      LAYER M4 ;
      RECT 0.000 128.880 0.024 128.904 ;
    END
  END rd_out_A[17]
  PIN rd_out_B[17]
    DIRECTION OUTPUT ;
    USE SIGNAL ;
    SHAPE ABUTMENT ;
    PORT
      LAYER M4 ;
      RECT 93.836 128.880 93.860 128.904 ;
    END
  END rd_out_B[17]
  PIN rd_out_A[18]
    DIRECTION OUTPUT ;
    USE SIGNAL ;
    SHAPE ABUTMENT ;
    PORT
      LAYER M4 ;
      RECT 0.000 130.464 0.024 130.488 ;
    END
  END rd_out_A[18]
  PIN rd_out_B[18]
    DIRECTION OUTPUT ;
    USE SIGNAL ;
    SHAPE ABUTMENT ;
    PORT
      LAYER M4 ;
      RECT 93.836 130.464 93.860 130.488 ;
    END
  END rd_out_B[18]
  PIN rd_out_A[19]
    DIRECTION OUTPUT ;
    USE SIGNAL ;
    SHAPE ABUTMENT ;
    PORT
      LAYER M4 ;
      RECT 0.000 132.048 0.024 132.072 ;
    END
  END rd_out_A[19]
  PIN rd_out_B[19]
    DIRECTION OUTPUT ;
    USE SIGNAL ;
    SHAPE ABUTMENT ;
    PORT
      LAYER M4 ;
      RECT 93.836 132.048 93.860 132.072 ;
    END
  END rd_out_B[19]
  PIN rd_out_A[20]
    DIRECTION OUTPUT ;
    USE SIGNAL ;
    SHAPE ABUTMENT ;
    PORT
      LAYER M4 ;
      RECT 0.000 133.632 0.024 133.656 ;
    END
  END rd_out_A[20]
  PIN rd_out_B[20]
    DIRECTION OUTPUT ;
    USE SIGNAL ;
    SHAPE ABUTMENT ;
    PORT
      LAYER M4 ;
      RECT 93.836 133.632 93.860 133.656 ;
    END
  END rd_out_B[20]
  PIN rd_out_A[21]
    DIRECTION OUTPUT ;
    USE SIGNAL ;
    SHAPE ABUTMENT ;
    PORT
      LAYER M4 ;
      RECT 0.000 135.216 0.024 135.240 ;
    END
  END rd_out_A[21]
  PIN rd_out_B[21]
    DIRECTION OUTPUT ;
    USE SIGNAL ;
    SHAPE ABUTMENT ;
    PORT
      LAYER M4 ;
      RECT 93.836 135.216 93.860 135.240 ;
    END
  END rd_out_B[21]
  PIN rd_out_A[22]
    DIRECTION OUTPUT ;
    USE SIGNAL ;
    SHAPE ABUTMENT ;
    PORT
      LAYER M4 ;
      RECT 0.000 136.800 0.024 136.824 ;
    END
  END rd_out_A[22]
  PIN rd_out_B[22]
    DIRECTION OUTPUT ;
    USE SIGNAL ;
    SHAPE ABUTMENT ;
    PORT
      LAYER M4 ;
      RECT 93.836 136.800 93.860 136.824 ;
    END
  END rd_out_B[22]
  PIN rd_out_A[23]
    DIRECTION OUTPUT ;
    USE SIGNAL ;
    SHAPE ABUTMENT ;
    PORT
      LAYER M4 ;
      RECT 0.000 138.384 0.024 138.408 ;
    END
  END rd_out_A[23]
  PIN rd_out_B[23]
    DIRECTION OUTPUT ;
    USE SIGNAL ;
    SHAPE ABUTMENT ;
    PORT
      LAYER M4 ;
      RECT 93.836 138.384 93.860 138.408 ;
    END
  END rd_out_B[23]
  PIN rd_out_A[24]
    DIRECTION OUTPUT ;
    USE SIGNAL ;
    SHAPE ABUTMENT ;
    PORT
      LAYER M4 ;
      RECT 0.000 139.968 0.024 139.992 ;
    END
  END rd_out_A[24]
  PIN rd_out_B[24]
    DIRECTION OUTPUT ;
    USE SIGNAL ;
    SHAPE ABUTMENT ;
    PORT
      LAYER M4 ;
      RECT 93.836 139.968 93.860 139.992 ;
    END
  END rd_out_B[24]
  PIN rd_out_A[25]
    DIRECTION OUTPUT ;
    USE SIGNAL ;
    SHAPE ABUTMENT ;
    PORT
      LAYER M4 ;
      RECT 0.000 141.552 0.024 141.576 ;
    END
  END rd_out_A[25]
  PIN rd_out_B[25]
    DIRECTION OUTPUT ;
    USE SIGNAL ;
    SHAPE ABUTMENT ;
    PORT
      LAYER M4 ;
      RECT 93.836 141.552 93.860 141.576 ;
    END
  END rd_out_B[25]
  PIN rd_out_A[26]
    DIRECTION OUTPUT ;
    USE SIGNAL ;
    SHAPE ABUTMENT ;
    PORT
      LAYER M4 ;
      RECT 0.000 143.136 0.024 143.160 ;
    END
  END rd_out_A[26]
  PIN rd_out_B[26]
    DIRECTION OUTPUT ;
    USE SIGNAL ;
    SHAPE ABUTMENT ;
    PORT
      LAYER M4 ;
      RECT 93.836 143.136 93.860 143.160 ;
    END
  END rd_out_B[26]
  PIN rd_out_A[27]
    DIRECTION OUTPUT ;
    USE SIGNAL ;
    SHAPE ABUTMENT ;
    PORT
      LAYER M4 ;
      RECT 0.000 144.720 0.024 144.744 ;
    END
  END rd_out_A[27]
  PIN rd_out_B[27]
    DIRECTION OUTPUT ;
    USE SIGNAL ;
    SHAPE ABUTMENT ;
    PORT
      LAYER M4 ;
      RECT 93.836 144.720 93.860 144.744 ;
    END
  END rd_out_B[27]
  PIN rd_out_A[28]
    DIRECTION OUTPUT ;
    USE SIGNAL ;
    SHAPE ABUTMENT ;
    PORT
      LAYER M4 ;
      RECT 0.000 146.304 0.024 146.328 ;
    END
  END rd_out_A[28]
  PIN rd_out_B[28]
    DIRECTION OUTPUT ;
    USE SIGNAL ;
    SHAPE ABUTMENT ;
    PORT
      LAYER M4 ;
      RECT 93.836 146.304 93.860 146.328 ;
    END
  END rd_out_B[28]
  PIN rd_out_A[29]
    DIRECTION OUTPUT ;
    USE SIGNAL ;
    SHAPE ABUTMENT ;
    PORT
      LAYER M4 ;
      RECT 0.000 147.888 0.024 147.912 ;
    END
  END rd_out_A[29]
  PIN rd_out_B[29]
    DIRECTION OUTPUT ;
    USE SIGNAL ;
    SHAPE ABUTMENT ;
    PORT
      LAYER M4 ;
      RECT 93.836 147.888 93.860 147.912 ;
    END
  END rd_out_B[29]
  PIN rd_out_A[30]
    DIRECTION OUTPUT ;
    USE SIGNAL ;
    SHAPE ABUTMENT ;
    PORT
      LAYER M4 ;
      RECT 0.000 149.472 0.024 149.496 ;
    END
  END rd_out_A[30]
  PIN rd_out_B[30]
    DIRECTION OUTPUT ;
    USE SIGNAL ;
    SHAPE ABUTMENT ;
    PORT
      LAYER M4 ;
      RECT 93.836 149.472 93.860 149.496 ;
    END
  END rd_out_B[30]
  PIN rd_out_A[31]
    DIRECTION OUTPUT ;
    USE SIGNAL ;
    SHAPE ABUTMENT ;
    PORT
      LAYER M4 ;
      RECT 0.000 151.056 0.024 151.080 ;
    END
  END rd_out_A[31]
  PIN rd_out_B[31]
    DIRECTION OUTPUT ;
    USE SIGNAL ;
    SHAPE ABUTMENT ;
    PORT
      LAYER M4 ;
      RECT 93.836 151.056 93.860 151.080 ;
    END
  END rd_out_B[31]
  PIN rd_out_A[32]
    DIRECTION OUTPUT ;
    USE SIGNAL ;
    SHAPE ABUTMENT ;
    PORT
      LAYER M4 ;
      RECT 0.000 152.640 0.024 152.664 ;
    END
  END rd_out_A[32]
  PIN rd_out_B[32]
    DIRECTION OUTPUT ;
    USE SIGNAL ;
    SHAPE ABUTMENT ;
    PORT
      LAYER M4 ;
      RECT 93.836 152.640 93.860 152.664 ;
    END
  END rd_out_B[32]
  PIN rd_out_A[33]
    DIRECTION OUTPUT ;
    USE SIGNAL ;
    SHAPE ABUTMENT ;
    PORT
      LAYER M4 ;
      RECT 0.000 154.224 0.024 154.248 ;
    END
  END rd_out_A[33]
  PIN rd_out_B[33]
    DIRECTION OUTPUT ;
    USE SIGNAL ;
    SHAPE ABUTMENT ;
    PORT
      LAYER M4 ;
      RECT 93.836 154.224 93.860 154.248 ;
    END
  END rd_out_B[33]
  PIN rd_out_A[34]
    DIRECTION OUTPUT ;
    USE SIGNAL ;
    SHAPE ABUTMENT ;
    PORT
      LAYER M4 ;
      RECT 0.000 155.808 0.024 155.832 ;
    END
  END rd_out_A[34]
  PIN rd_out_B[34]
    DIRECTION OUTPUT ;
    USE SIGNAL ;
    SHAPE ABUTMENT ;
    PORT
      LAYER M4 ;
      RECT 93.836 155.808 93.860 155.832 ;
    END
  END rd_out_B[34]
  PIN rd_out_A[35]
    DIRECTION OUTPUT ;
    USE SIGNAL ;
    SHAPE ABUTMENT ;
    PORT
      LAYER M4 ;
      RECT 0.000 157.392 0.024 157.416 ;
    END
  END rd_out_A[35]
  PIN rd_out_B[35]
    DIRECTION OUTPUT ;
    USE SIGNAL ;
    SHAPE ABUTMENT ;
    PORT
      LAYER M4 ;
      RECT 93.836 157.392 93.860 157.416 ;
    END
  END rd_out_B[35]
  PIN rd_out_A[36]
    DIRECTION OUTPUT ;
    USE SIGNAL ;
    SHAPE ABUTMENT ;
    PORT
      LAYER M4 ;
      RECT 0.000 158.976 0.024 159.000 ;
    END
  END rd_out_A[36]
  PIN rd_out_B[36]
    DIRECTION OUTPUT ;
    USE SIGNAL ;
    SHAPE ABUTMENT ;
    PORT
      LAYER M4 ;
      RECT 93.836 158.976 93.860 159.000 ;
    END
  END rd_out_B[36]
  PIN rd_out_A[37]
    DIRECTION OUTPUT ;
    USE SIGNAL ;
    SHAPE ABUTMENT ;
    PORT
      LAYER M4 ;
      RECT 0.000 160.560 0.024 160.584 ;
    END
  END rd_out_A[37]
  PIN rd_out_B[37]
    DIRECTION OUTPUT ;
    USE SIGNAL ;
    SHAPE ABUTMENT ;
    PORT
      LAYER M4 ;
      RECT 93.836 160.560 93.860 160.584 ;
    END
  END rd_out_B[37]
  PIN rd_out_A[38]
    DIRECTION OUTPUT ;
    USE SIGNAL ;
    SHAPE ABUTMENT ;
    PORT
      LAYER M4 ;
      RECT 0.000 162.144 0.024 162.168 ;
    END
  END rd_out_A[38]
  PIN rd_out_B[38]
    DIRECTION OUTPUT ;
    USE SIGNAL ;
    SHAPE ABUTMENT ;
    PORT
      LAYER M4 ;
      RECT 93.836 162.144 93.860 162.168 ;
    END
  END rd_out_B[38]
  PIN rd_out_A[39]
    DIRECTION OUTPUT ;
    USE SIGNAL ;
    SHAPE ABUTMENT ;
    PORT
      LAYER M4 ;
      RECT 0.000 163.728 0.024 163.752 ;
    END
  END rd_out_A[39]
  PIN rd_out_B[39]
    DIRECTION OUTPUT ;
    USE SIGNAL ;
    SHAPE ABUTMENT ;
    PORT
      LAYER M4 ;
      RECT 93.836 163.728 93.860 163.752 ;
    END
  END rd_out_B[39]
  PIN rd_out_A[40]
    DIRECTION OUTPUT ;
    USE SIGNAL ;
    SHAPE ABUTMENT ;
    PORT
      LAYER M4 ;
      RECT 0.000 165.312 0.024 165.336 ;
    END
  END rd_out_A[40]
  PIN rd_out_B[40]
    DIRECTION OUTPUT ;
    USE SIGNAL ;
    SHAPE ABUTMENT ;
    PORT
      LAYER M4 ;
      RECT 93.836 165.312 93.860 165.336 ;
    END
  END rd_out_B[40]
  PIN rd_out_A[41]
    DIRECTION OUTPUT ;
    USE SIGNAL ;
    SHAPE ABUTMENT ;
    PORT
      LAYER M4 ;
      RECT 0.000 166.896 0.024 166.920 ;
    END
  END rd_out_A[41]
  PIN rd_out_B[41]
    DIRECTION OUTPUT ;
    USE SIGNAL ;
    SHAPE ABUTMENT ;
    PORT
      LAYER M4 ;
      RECT 93.836 166.896 93.860 166.920 ;
    END
  END rd_out_B[41]
  PIN rd_out_A[42]
    DIRECTION OUTPUT ;
    USE SIGNAL ;
    SHAPE ABUTMENT ;
    PORT
      LAYER M4 ;
      RECT 0.000 168.480 0.024 168.504 ;
    END
  END rd_out_A[42]
  PIN rd_out_B[42]
    DIRECTION OUTPUT ;
    USE SIGNAL ;
    SHAPE ABUTMENT ;
    PORT
      LAYER M4 ;
      RECT 93.836 168.480 93.860 168.504 ;
    END
  END rd_out_B[42]
  PIN rd_out_A[43]
    DIRECTION OUTPUT ;
    USE SIGNAL ;
    SHAPE ABUTMENT ;
    PORT
      LAYER M4 ;
      RECT 0.000 170.064 0.024 170.088 ;
    END
  END rd_out_A[43]
  PIN rd_out_B[43]
    DIRECTION OUTPUT ;
    USE SIGNAL ;
    SHAPE ABUTMENT ;
    PORT
      LAYER M4 ;
      RECT 93.836 170.064 93.860 170.088 ;
    END
  END rd_out_B[43]
  PIN rd_out_A[44]
    DIRECTION OUTPUT ;
    USE SIGNAL ;
    SHAPE ABUTMENT ;
    PORT
      LAYER M4 ;
      RECT 0.000 171.648 0.024 171.672 ;
    END
  END rd_out_A[44]
  PIN rd_out_B[44]
    DIRECTION OUTPUT ;
    USE SIGNAL ;
    SHAPE ABUTMENT ;
    PORT
      LAYER M4 ;
      RECT 93.836 171.648 93.860 171.672 ;
    END
  END rd_out_B[44]
  PIN rd_out_A[45]
    DIRECTION OUTPUT ;
    USE SIGNAL ;
    SHAPE ABUTMENT ;
    PORT
      LAYER M4 ;
      RECT 0.000 173.232 0.024 173.256 ;
    END
  END rd_out_A[45]
  PIN rd_out_B[45]
    DIRECTION OUTPUT ;
    USE SIGNAL ;
    SHAPE ABUTMENT ;
    PORT
      LAYER M4 ;
      RECT 93.836 173.232 93.860 173.256 ;
    END
  END rd_out_B[45]
  PIN rd_out_A[46]
    DIRECTION OUTPUT ;
    USE SIGNAL ;
    SHAPE ABUTMENT ;
    PORT
      LAYER M4 ;
      RECT 0.000 174.816 0.024 174.840 ;
    END
  END rd_out_A[46]
  PIN rd_out_B[46]
    DIRECTION OUTPUT ;
    USE SIGNAL ;
    SHAPE ABUTMENT ;
    PORT
      LAYER M4 ;
      RECT 93.836 174.816 93.860 174.840 ;
    END
  END rd_out_B[46]
  PIN rd_out_A[47]
    DIRECTION OUTPUT ;
    USE SIGNAL ;
    SHAPE ABUTMENT ;
    PORT
      LAYER M4 ;
      RECT 0.000 176.400 0.024 176.424 ;
    END
  END rd_out_A[47]
  PIN rd_out_B[47]
    DIRECTION OUTPUT ;
    USE SIGNAL ;
    SHAPE ABUTMENT ;
    PORT
      LAYER M4 ;
      RECT 93.836 176.400 93.860 176.424 ;
    END
  END rd_out_B[47]
  PIN rd_out_A[48]
    DIRECTION OUTPUT ;
    USE SIGNAL ;
    SHAPE ABUTMENT ;
    PORT
      LAYER M4 ;
      RECT 0.000 177.984 0.024 178.008 ;
    END
  END rd_out_A[48]
  PIN rd_out_B[48]
    DIRECTION OUTPUT ;
    USE SIGNAL ;
    SHAPE ABUTMENT ;
    PORT
      LAYER M4 ;
      RECT 93.836 177.984 93.860 178.008 ;
    END
  END rd_out_B[48]
  PIN rd_out_A[49]
    DIRECTION OUTPUT ;
    USE SIGNAL ;
    SHAPE ABUTMENT ;
    PORT
      LAYER M4 ;
      RECT 0.000 179.568 0.024 179.592 ;
    END
  END rd_out_A[49]
  PIN rd_out_B[49]
    DIRECTION OUTPUT ;
    USE SIGNAL ;
    SHAPE ABUTMENT ;
    PORT
      LAYER M4 ;
      RECT 93.836 179.568 93.860 179.592 ;
    END
  END rd_out_B[49]
  PIN rd_out_A[50]
    DIRECTION OUTPUT ;
    USE SIGNAL ;
    SHAPE ABUTMENT ;
    PORT
      LAYER M4 ;
      RECT 0.000 181.152 0.024 181.176 ;
    END
  END rd_out_A[50]
  PIN rd_out_B[50]
    DIRECTION OUTPUT ;
    USE SIGNAL ;
    SHAPE ABUTMENT ;
    PORT
      LAYER M4 ;
      RECT 93.836 181.152 93.860 181.176 ;
    END
  END rd_out_B[50]
  PIN rd_out_A[51]
    DIRECTION OUTPUT ;
    USE SIGNAL ;
    SHAPE ABUTMENT ;
    PORT
      LAYER M4 ;
      RECT 0.000 182.736 0.024 182.760 ;
    END
  END rd_out_A[51]
  PIN rd_out_B[51]
    DIRECTION OUTPUT ;
    USE SIGNAL ;
    SHAPE ABUTMENT ;
    PORT
      LAYER M4 ;
      RECT 93.836 182.736 93.860 182.760 ;
    END
  END rd_out_B[51]
  PIN rd_out_A[52]
    DIRECTION OUTPUT ;
    USE SIGNAL ;
    SHAPE ABUTMENT ;
    PORT
      LAYER M4 ;
      RECT 0.000 184.320 0.024 184.344 ;
    END
  END rd_out_A[52]
  PIN rd_out_B[52]
    DIRECTION OUTPUT ;
    USE SIGNAL ;
    SHAPE ABUTMENT ;
    PORT
      LAYER M4 ;
      RECT 93.836 184.320 93.860 184.344 ;
    END
  END rd_out_B[52]
  PIN rd_out_A[53]
    DIRECTION OUTPUT ;
    USE SIGNAL ;
    SHAPE ABUTMENT ;
    PORT
      LAYER M4 ;
      RECT 0.000 185.904 0.024 185.928 ;
    END
  END rd_out_A[53]
  PIN rd_out_B[53]
    DIRECTION OUTPUT ;
    USE SIGNAL ;
    SHAPE ABUTMENT ;
    PORT
      LAYER M4 ;
      RECT 93.836 185.904 93.860 185.928 ;
    END
  END rd_out_B[53]
  PIN rd_out_A[54]
    DIRECTION OUTPUT ;
    USE SIGNAL ;
    SHAPE ABUTMENT ;
    PORT
      LAYER M4 ;
      RECT 0.000 187.488 0.024 187.512 ;
    END
  END rd_out_A[54]
  PIN rd_out_B[54]
    DIRECTION OUTPUT ;
    USE SIGNAL ;
    SHAPE ABUTMENT ;
    PORT
      LAYER M4 ;
      RECT 93.836 187.488 93.860 187.512 ;
    END
  END rd_out_B[54]
  PIN rd_out_A[55]
    DIRECTION OUTPUT ;
    USE SIGNAL ;
    SHAPE ABUTMENT ;
    PORT
      LAYER M4 ;
      RECT 0.000 189.072 0.024 189.096 ;
    END
  END rd_out_A[55]
  PIN rd_out_B[55]
    DIRECTION OUTPUT ;
    USE SIGNAL ;
    SHAPE ABUTMENT ;
    PORT
      LAYER M4 ;
      RECT 93.836 189.072 93.860 189.096 ;
    END
  END rd_out_B[55]
  PIN rd_out_A[56]
    DIRECTION OUTPUT ;
    USE SIGNAL ;
    SHAPE ABUTMENT ;
    PORT
      LAYER M4 ;
      RECT 0.000 190.656 0.024 190.680 ;
    END
  END rd_out_A[56]
  PIN rd_out_B[56]
    DIRECTION OUTPUT ;
    USE SIGNAL ;
    SHAPE ABUTMENT ;
    PORT
      LAYER M4 ;
      RECT 93.836 190.656 93.860 190.680 ;
    END
  END rd_out_B[56]
  PIN rd_out_A[57]
    DIRECTION OUTPUT ;
    USE SIGNAL ;
    SHAPE ABUTMENT ;
    PORT
      LAYER M4 ;
      RECT 0.000 192.240 0.024 192.264 ;
    END
  END rd_out_A[57]
  PIN rd_out_B[57]
    DIRECTION OUTPUT ;
    USE SIGNAL ;
    SHAPE ABUTMENT ;
    PORT
      LAYER M4 ;
      RECT 93.836 192.240 93.860 192.264 ;
    END
  END rd_out_B[57]
  PIN rd_out_A[58]
    DIRECTION OUTPUT ;
    USE SIGNAL ;
    SHAPE ABUTMENT ;
    PORT
      LAYER M4 ;
      RECT 0.000 193.824 0.024 193.848 ;
    END
  END rd_out_A[58]
  PIN rd_out_B[58]
    DIRECTION OUTPUT ;
    USE SIGNAL ;
    SHAPE ABUTMENT ;
    PORT
      LAYER M4 ;
      RECT 93.836 193.824 93.860 193.848 ;
    END
  END rd_out_B[58]
  PIN rd_out_A[59]
    DIRECTION OUTPUT ;
    USE SIGNAL ;
    SHAPE ABUTMENT ;
    PORT
      LAYER M4 ;
      RECT 0.000 195.408 0.024 195.432 ;
    END
  END rd_out_A[59]
  PIN rd_out_B[59]
    DIRECTION OUTPUT ;
    USE SIGNAL ;
    SHAPE ABUTMENT ;
    PORT
      LAYER M4 ;
      RECT 93.836 195.408 93.860 195.432 ;
    END
  END rd_out_B[59]
  PIN rd_out_A[60]
    DIRECTION OUTPUT ;
    USE SIGNAL ;
    SHAPE ABUTMENT ;
    PORT
      LAYER M4 ;
      RECT 0.000 196.992 0.024 197.016 ;
    END
  END rd_out_A[60]
  PIN rd_out_B[60]
    DIRECTION OUTPUT ;
    USE SIGNAL ;
    SHAPE ABUTMENT ;
    PORT
      LAYER M4 ;
      RECT 93.836 196.992 93.860 197.016 ;
    END
  END rd_out_B[60]
  PIN rd_out_A[61]
    DIRECTION OUTPUT ;
    USE SIGNAL ;
    SHAPE ABUTMENT ;
    PORT
      LAYER M4 ;
      RECT 0.000 198.576 0.024 198.600 ;
    END
  END rd_out_A[61]
  PIN rd_out_B[61]
    DIRECTION OUTPUT ;
    USE SIGNAL ;
    SHAPE ABUTMENT ;
    PORT
      LAYER M4 ;
      RECT 93.836 198.576 93.860 198.600 ;
    END
  END rd_out_B[61]
  PIN rd_out_A[62]
    DIRECTION OUTPUT ;
    USE SIGNAL ;
    SHAPE ABUTMENT ;
    PORT
      LAYER M4 ;
      RECT 0.000 200.160 0.024 200.184 ;
    END
  END rd_out_A[62]
  PIN rd_out_B[62]
    DIRECTION OUTPUT ;
    USE SIGNAL ;
    SHAPE ABUTMENT ;
    PORT
      LAYER M4 ;
      RECT 93.836 200.160 93.860 200.184 ;
    END
  END rd_out_B[62]
  PIN rd_out_A[63]
    DIRECTION OUTPUT ;
    USE SIGNAL ;
    SHAPE ABUTMENT ;
    PORT
      LAYER M4 ;
      RECT 0.000 201.744 0.024 201.768 ;
    END
  END rd_out_A[63]
  PIN rd_out_B[63]
    DIRECTION OUTPUT ;
    USE SIGNAL ;
    SHAPE ABUTMENT ;
    PORT
      LAYER M4 ;
      RECT 93.836 201.744 93.860 201.768 ;
    END
  END rd_out_B[63]
  PIN wd_in_A[0]
    DIRECTION INPUT ;
    USE SIGNAL ;
    SHAPE ABUTMENT ;
    PORT
      LAYER M4 ;
      RECT 0.000 203.856 0.024 203.880 ;
    END
  END wd_in_A[0]
  PIN wd_in_B[0]
    DIRECTION INPUT ;
    USE SIGNAL ;
    SHAPE ABUTMENT ;
    PORT
      LAYER M4 ;
      RECT 93.836 203.856 93.860 203.880 ;
    END
  END wd_in_B[0]
  PIN wd_in_A[1]
    DIRECTION INPUT ;
    USE SIGNAL ;
    SHAPE ABUTMENT ;
    PORT
      LAYER M4 ;
      RECT 0.000 205.440 0.024 205.464 ;
    END
  END wd_in_A[1]
  PIN wd_in_B[1]
    DIRECTION INPUT ;
    USE SIGNAL ;
    SHAPE ABUTMENT ;
    PORT
      LAYER M4 ;
      RECT 93.836 205.440 93.860 205.464 ;
    END
  END wd_in_B[1]
  PIN wd_in_A[2]
    DIRECTION INPUT ;
    USE SIGNAL ;
    SHAPE ABUTMENT ;
    PORT
      LAYER M4 ;
      RECT 0.000 207.024 0.024 207.048 ;
    END
  END wd_in_A[2]
  PIN wd_in_B[2]
    DIRECTION INPUT ;
    USE SIGNAL ;
    SHAPE ABUTMENT ;
    PORT
      LAYER M4 ;
      RECT 93.836 207.024 93.860 207.048 ;
    END
  END wd_in_B[2]
  PIN wd_in_A[3]
    DIRECTION INPUT ;
    USE SIGNAL ;
    SHAPE ABUTMENT ;
    PORT
      LAYER M4 ;
      RECT 0.000 208.608 0.024 208.632 ;
    END
  END wd_in_A[3]
  PIN wd_in_B[3]
    DIRECTION INPUT ;
    USE SIGNAL ;
    SHAPE ABUTMENT ;
    PORT
      LAYER M4 ;
      RECT 93.836 208.608 93.860 208.632 ;
    END
  END wd_in_B[3]
  PIN wd_in_A[4]
    DIRECTION INPUT ;
    USE SIGNAL ;
    SHAPE ABUTMENT ;
    PORT
      LAYER M4 ;
      RECT 0.000 210.192 0.024 210.216 ;
    END
  END wd_in_A[4]
  PIN wd_in_B[4]
    DIRECTION INPUT ;
    USE SIGNAL ;
    SHAPE ABUTMENT ;
    PORT
      LAYER M4 ;
      RECT 93.836 210.192 93.860 210.216 ;
    END
  END wd_in_B[4]
  PIN wd_in_A[5]
    DIRECTION INPUT ;
    USE SIGNAL ;
    SHAPE ABUTMENT ;
    PORT
      LAYER M4 ;
      RECT 0.000 211.776 0.024 211.800 ;
    END
  END wd_in_A[5]
  PIN wd_in_B[5]
    DIRECTION INPUT ;
    USE SIGNAL ;
    SHAPE ABUTMENT ;
    PORT
      LAYER M4 ;
      RECT 93.836 211.776 93.860 211.800 ;
    END
  END wd_in_B[5]
  PIN wd_in_A[6]
    DIRECTION INPUT ;
    USE SIGNAL ;
    SHAPE ABUTMENT ;
    PORT
      LAYER M4 ;
      RECT 0.000 213.360 0.024 213.384 ;
    END
  END wd_in_A[6]
  PIN wd_in_B[6]
    DIRECTION INPUT ;
    USE SIGNAL ;
    SHAPE ABUTMENT ;
    PORT
      LAYER M4 ;
      RECT 93.836 213.360 93.860 213.384 ;
    END
  END wd_in_B[6]
  PIN wd_in_A[7]
    DIRECTION INPUT ;
    USE SIGNAL ;
    SHAPE ABUTMENT ;
    PORT
      LAYER M4 ;
      RECT 0.000 214.944 0.024 214.968 ;
    END
  END wd_in_A[7]
  PIN wd_in_B[7]
    DIRECTION INPUT ;
    USE SIGNAL ;
    SHAPE ABUTMENT ;
    PORT
      LAYER M4 ;
      RECT 93.836 214.944 93.860 214.968 ;
    END
  END wd_in_B[7]
  PIN wd_in_A[8]
    DIRECTION INPUT ;
    USE SIGNAL ;
    SHAPE ABUTMENT ;
    PORT
      LAYER M4 ;
      RECT 0.000 216.528 0.024 216.552 ;
    END
  END wd_in_A[8]
  PIN wd_in_B[8]
    DIRECTION INPUT ;
    USE SIGNAL ;
    SHAPE ABUTMENT ;
    PORT
      LAYER M4 ;
      RECT 93.836 216.528 93.860 216.552 ;
    END
  END wd_in_B[8]
  PIN wd_in_A[9]
    DIRECTION INPUT ;
    USE SIGNAL ;
    SHAPE ABUTMENT ;
    PORT
      LAYER M4 ;
      RECT 0.000 218.112 0.024 218.136 ;
    END
  END wd_in_A[9]
  PIN wd_in_B[9]
    DIRECTION INPUT ;
    USE SIGNAL ;
    SHAPE ABUTMENT ;
    PORT
      LAYER M4 ;
      RECT 93.836 218.112 93.860 218.136 ;
    END
  END wd_in_B[9]
  PIN wd_in_A[10]
    DIRECTION INPUT ;
    USE SIGNAL ;
    SHAPE ABUTMENT ;
    PORT
      LAYER M4 ;
      RECT 0.000 219.696 0.024 219.720 ;
    END
  END wd_in_A[10]
  PIN wd_in_B[10]
    DIRECTION INPUT ;
    USE SIGNAL ;
    SHAPE ABUTMENT ;
    PORT
      LAYER M4 ;
      RECT 93.836 219.696 93.860 219.720 ;
    END
  END wd_in_B[10]
  PIN wd_in_A[11]
    DIRECTION INPUT ;
    USE SIGNAL ;
    SHAPE ABUTMENT ;
    PORT
      LAYER M4 ;
      RECT 0.000 221.280 0.024 221.304 ;
    END
  END wd_in_A[11]
  PIN wd_in_B[11]
    DIRECTION INPUT ;
    USE SIGNAL ;
    SHAPE ABUTMENT ;
    PORT
      LAYER M4 ;
      RECT 93.836 221.280 93.860 221.304 ;
    END
  END wd_in_B[11]
  PIN wd_in_A[12]
    DIRECTION INPUT ;
    USE SIGNAL ;
    SHAPE ABUTMENT ;
    PORT
      LAYER M4 ;
      RECT 0.000 222.864 0.024 222.888 ;
    END
  END wd_in_A[12]
  PIN wd_in_B[12]
    DIRECTION INPUT ;
    USE SIGNAL ;
    SHAPE ABUTMENT ;
    PORT
      LAYER M4 ;
      RECT 93.836 222.864 93.860 222.888 ;
    END
  END wd_in_B[12]
  PIN wd_in_A[13]
    DIRECTION INPUT ;
    USE SIGNAL ;
    SHAPE ABUTMENT ;
    PORT
      LAYER M4 ;
      RECT 0.000 224.448 0.024 224.472 ;
    END
  END wd_in_A[13]
  PIN wd_in_B[13]
    DIRECTION INPUT ;
    USE SIGNAL ;
    SHAPE ABUTMENT ;
    PORT
      LAYER M4 ;
      RECT 93.836 224.448 93.860 224.472 ;
    END
  END wd_in_B[13]
  PIN wd_in_A[14]
    DIRECTION INPUT ;
    USE SIGNAL ;
    SHAPE ABUTMENT ;
    PORT
      LAYER M4 ;
      RECT 0.000 226.032 0.024 226.056 ;
    END
  END wd_in_A[14]
  PIN wd_in_B[14]
    DIRECTION INPUT ;
    USE SIGNAL ;
    SHAPE ABUTMENT ;
    PORT
      LAYER M4 ;
      RECT 93.836 226.032 93.860 226.056 ;
    END
  END wd_in_B[14]
  PIN wd_in_A[15]
    DIRECTION INPUT ;
    USE SIGNAL ;
    SHAPE ABUTMENT ;
    PORT
      LAYER M4 ;
      RECT 0.000 227.616 0.024 227.640 ;
    END
  END wd_in_A[15]
  PIN wd_in_B[15]
    DIRECTION INPUT ;
    USE SIGNAL ;
    SHAPE ABUTMENT ;
    PORT
      LAYER M4 ;
      RECT 93.836 227.616 93.860 227.640 ;
    END
  END wd_in_B[15]
  PIN wd_in_A[16]
    DIRECTION INPUT ;
    USE SIGNAL ;
    SHAPE ABUTMENT ;
    PORT
      LAYER M4 ;
      RECT 0.000 229.200 0.024 229.224 ;
    END
  END wd_in_A[16]
  PIN wd_in_B[16]
    DIRECTION INPUT ;
    USE SIGNAL ;
    SHAPE ABUTMENT ;
    PORT
      LAYER M4 ;
      RECT 93.836 229.200 93.860 229.224 ;
    END
  END wd_in_B[16]
  PIN wd_in_A[17]
    DIRECTION INPUT ;
    USE SIGNAL ;
    SHAPE ABUTMENT ;
    PORT
      LAYER M4 ;
      RECT 0.000 230.784 0.024 230.808 ;
    END
  END wd_in_A[17]
  PIN wd_in_B[17]
    DIRECTION INPUT ;
    USE SIGNAL ;
    SHAPE ABUTMENT ;
    PORT
      LAYER M4 ;
      RECT 93.836 230.784 93.860 230.808 ;
    END
  END wd_in_B[17]
  PIN wd_in_A[18]
    DIRECTION INPUT ;
    USE SIGNAL ;
    SHAPE ABUTMENT ;
    PORT
      LAYER M4 ;
      RECT 0.000 232.368 0.024 232.392 ;
    END
  END wd_in_A[18]
  PIN wd_in_B[18]
    DIRECTION INPUT ;
    USE SIGNAL ;
    SHAPE ABUTMENT ;
    PORT
      LAYER M4 ;
      RECT 93.836 232.368 93.860 232.392 ;
    END
  END wd_in_B[18]
  PIN wd_in_A[19]
    DIRECTION INPUT ;
    USE SIGNAL ;
    SHAPE ABUTMENT ;
    PORT
      LAYER M4 ;
      RECT 0.000 233.952 0.024 233.976 ;
    END
  END wd_in_A[19]
  PIN wd_in_B[19]
    DIRECTION INPUT ;
    USE SIGNAL ;
    SHAPE ABUTMENT ;
    PORT
      LAYER M4 ;
      RECT 93.836 233.952 93.860 233.976 ;
    END
  END wd_in_B[19]
  PIN wd_in_A[20]
    DIRECTION INPUT ;
    USE SIGNAL ;
    SHAPE ABUTMENT ;
    PORT
      LAYER M4 ;
      RECT 0.000 235.536 0.024 235.560 ;
    END
  END wd_in_A[20]
  PIN wd_in_B[20]
    DIRECTION INPUT ;
    USE SIGNAL ;
    SHAPE ABUTMENT ;
    PORT
      LAYER M4 ;
      RECT 93.836 235.536 93.860 235.560 ;
    END
  END wd_in_B[20]
  PIN wd_in_A[21]
    DIRECTION INPUT ;
    USE SIGNAL ;
    SHAPE ABUTMENT ;
    PORT
      LAYER M4 ;
      RECT 0.000 237.120 0.024 237.144 ;
    END
  END wd_in_A[21]
  PIN wd_in_B[21]
    DIRECTION INPUT ;
    USE SIGNAL ;
    SHAPE ABUTMENT ;
    PORT
      LAYER M4 ;
      RECT 93.836 237.120 93.860 237.144 ;
    END
  END wd_in_B[21]
  PIN wd_in_A[22]
    DIRECTION INPUT ;
    USE SIGNAL ;
    SHAPE ABUTMENT ;
    PORT
      LAYER M4 ;
      RECT 0.000 238.704 0.024 238.728 ;
    END
  END wd_in_A[22]
  PIN wd_in_B[22]
    DIRECTION INPUT ;
    USE SIGNAL ;
    SHAPE ABUTMENT ;
    PORT
      LAYER M4 ;
      RECT 93.836 238.704 93.860 238.728 ;
    END
  END wd_in_B[22]
  PIN wd_in_A[23]
    DIRECTION INPUT ;
    USE SIGNAL ;
    SHAPE ABUTMENT ;
    PORT
      LAYER M4 ;
      RECT 0.000 240.288 0.024 240.312 ;
    END
  END wd_in_A[23]
  PIN wd_in_B[23]
    DIRECTION INPUT ;
    USE SIGNAL ;
    SHAPE ABUTMENT ;
    PORT
      LAYER M4 ;
      RECT 93.836 240.288 93.860 240.312 ;
    END
  END wd_in_B[23]
  PIN wd_in_A[24]
    DIRECTION INPUT ;
    USE SIGNAL ;
    SHAPE ABUTMENT ;
    PORT
      LAYER M4 ;
      RECT 0.000 241.872 0.024 241.896 ;
    END
  END wd_in_A[24]
  PIN wd_in_B[24]
    DIRECTION INPUT ;
    USE SIGNAL ;
    SHAPE ABUTMENT ;
    PORT
      LAYER M4 ;
      RECT 93.836 241.872 93.860 241.896 ;
    END
  END wd_in_B[24]
  PIN wd_in_A[25]
    DIRECTION INPUT ;
    USE SIGNAL ;
    SHAPE ABUTMENT ;
    PORT
      LAYER M4 ;
      RECT 0.000 243.456 0.024 243.480 ;
    END
  END wd_in_A[25]
  PIN wd_in_B[25]
    DIRECTION INPUT ;
    USE SIGNAL ;
    SHAPE ABUTMENT ;
    PORT
      LAYER M4 ;
      RECT 93.836 243.456 93.860 243.480 ;
    END
  END wd_in_B[25]
  PIN wd_in_A[26]
    DIRECTION INPUT ;
    USE SIGNAL ;
    SHAPE ABUTMENT ;
    PORT
      LAYER M4 ;
      RECT 0.000 245.040 0.024 245.064 ;
    END
  END wd_in_A[26]
  PIN wd_in_B[26]
    DIRECTION INPUT ;
    USE SIGNAL ;
    SHAPE ABUTMENT ;
    PORT
      LAYER M4 ;
      RECT 93.836 245.040 93.860 245.064 ;
    END
  END wd_in_B[26]
  PIN wd_in_A[27]
    DIRECTION INPUT ;
    USE SIGNAL ;
    SHAPE ABUTMENT ;
    PORT
      LAYER M4 ;
      RECT 0.000 246.624 0.024 246.648 ;
    END
  END wd_in_A[27]
  PIN wd_in_B[27]
    DIRECTION INPUT ;
    USE SIGNAL ;
    SHAPE ABUTMENT ;
    PORT
      LAYER M4 ;
      RECT 93.836 246.624 93.860 246.648 ;
    END
  END wd_in_B[27]
  PIN wd_in_A[28]
    DIRECTION INPUT ;
    USE SIGNAL ;
    SHAPE ABUTMENT ;
    PORT
      LAYER M4 ;
      RECT 0.000 248.208 0.024 248.232 ;
    END
  END wd_in_A[28]
  PIN wd_in_B[28]
    DIRECTION INPUT ;
    USE SIGNAL ;
    SHAPE ABUTMENT ;
    PORT
      LAYER M4 ;
      RECT 93.836 248.208 93.860 248.232 ;
    END
  END wd_in_B[28]
  PIN wd_in_A[29]
    DIRECTION INPUT ;
    USE SIGNAL ;
    SHAPE ABUTMENT ;
    PORT
      LAYER M4 ;
      RECT 0.000 249.792 0.024 249.816 ;
    END
  END wd_in_A[29]
  PIN wd_in_B[29]
    DIRECTION INPUT ;
    USE SIGNAL ;
    SHAPE ABUTMENT ;
    PORT
      LAYER M4 ;
      RECT 93.836 249.792 93.860 249.816 ;
    END
  END wd_in_B[29]
  PIN wd_in_A[30]
    DIRECTION INPUT ;
    USE SIGNAL ;
    SHAPE ABUTMENT ;
    PORT
      LAYER M4 ;
      RECT 0.000 251.376 0.024 251.400 ;
    END
  END wd_in_A[30]
  PIN wd_in_B[30]
    DIRECTION INPUT ;
    USE SIGNAL ;
    SHAPE ABUTMENT ;
    PORT
      LAYER M4 ;
      RECT 93.836 251.376 93.860 251.400 ;
    END
  END wd_in_B[30]
  PIN wd_in_A[31]
    DIRECTION INPUT ;
    USE SIGNAL ;
    SHAPE ABUTMENT ;
    PORT
      LAYER M4 ;
      RECT 0.000 252.960 0.024 252.984 ;
    END
  END wd_in_A[31]
  PIN wd_in_B[31]
    DIRECTION INPUT ;
    USE SIGNAL ;
    SHAPE ABUTMENT ;
    PORT
      LAYER M4 ;
      RECT 93.836 252.960 93.860 252.984 ;
    END
  END wd_in_B[31]
  PIN wd_in_A[32]
    DIRECTION INPUT ;
    USE SIGNAL ;
    SHAPE ABUTMENT ;
    PORT
      LAYER M4 ;
      RECT 0.000 254.544 0.024 254.568 ;
    END
  END wd_in_A[32]
  PIN wd_in_B[32]
    DIRECTION INPUT ;
    USE SIGNAL ;
    SHAPE ABUTMENT ;
    PORT
      LAYER M4 ;
      RECT 93.836 254.544 93.860 254.568 ;
    END
  END wd_in_B[32]
  PIN wd_in_A[33]
    DIRECTION INPUT ;
    USE SIGNAL ;
    SHAPE ABUTMENT ;
    PORT
      LAYER M4 ;
      RECT 0.000 256.128 0.024 256.152 ;
    END
  END wd_in_A[33]
  PIN wd_in_B[33]
    DIRECTION INPUT ;
    USE SIGNAL ;
    SHAPE ABUTMENT ;
    PORT
      LAYER M4 ;
      RECT 93.836 256.128 93.860 256.152 ;
    END
  END wd_in_B[33]
  PIN wd_in_A[34]
    DIRECTION INPUT ;
    USE SIGNAL ;
    SHAPE ABUTMENT ;
    PORT
      LAYER M4 ;
      RECT 0.000 257.712 0.024 257.736 ;
    END
  END wd_in_A[34]
  PIN wd_in_B[34]
    DIRECTION INPUT ;
    USE SIGNAL ;
    SHAPE ABUTMENT ;
    PORT
      LAYER M4 ;
      RECT 93.836 257.712 93.860 257.736 ;
    END
  END wd_in_B[34]
  PIN wd_in_A[35]
    DIRECTION INPUT ;
    USE SIGNAL ;
    SHAPE ABUTMENT ;
    PORT
      LAYER M4 ;
      RECT 0.000 259.296 0.024 259.320 ;
    END
  END wd_in_A[35]
  PIN wd_in_B[35]
    DIRECTION INPUT ;
    USE SIGNAL ;
    SHAPE ABUTMENT ;
    PORT
      LAYER M4 ;
      RECT 93.836 259.296 93.860 259.320 ;
    END
  END wd_in_B[35]
  PIN wd_in_A[36]
    DIRECTION INPUT ;
    USE SIGNAL ;
    SHAPE ABUTMENT ;
    PORT
      LAYER M4 ;
      RECT 0.000 260.880 0.024 260.904 ;
    END
  END wd_in_A[36]
  PIN wd_in_B[36]
    DIRECTION INPUT ;
    USE SIGNAL ;
    SHAPE ABUTMENT ;
    PORT
      LAYER M4 ;
      RECT 93.836 260.880 93.860 260.904 ;
    END
  END wd_in_B[36]
  PIN wd_in_A[37]
    DIRECTION INPUT ;
    USE SIGNAL ;
    SHAPE ABUTMENT ;
    PORT
      LAYER M4 ;
      RECT 0.000 262.464 0.024 262.488 ;
    END
  END wd_in_A[37]
  PIN wd_in_B[37]
    DIRECTION INPUT ;
    USE SIGNAL ;
    SHAPE ABUTMENT ;
    PORT
      LAYER M4 ;
      RECT 93.836 262.464 93.860 262.488 ;
    END
  END wd_in_B[37]
  PIN wd_in_A[38]
    DIRECTION INPUT ;
    USE SIGNAL ;
    SHAPE ABUTMENT ;
    PORT
      LAYER M4 ;
      RECT 0.000 264.048 0.024 264.072 ;
    END
  END wd_in_A[38]
  PIN wd_in_B[38]
    DIRECTION INPUT ;
    USE SIGNAL ;
    SHAPE ABUTMENT ;
    PORT
      LAYER M4 ;
      RECT 93.836 264.048 93.860 264.072 ;
    END
  END wd_in_B[38]
  PIN wd_in_A[39]
    DIRECTION INPUT ;
    USE SIGNAL ;
    SHAPE ABUTMENT ;
    PORT
      LAYER M4 ;
      RECT 0.000 265.632 0.024 265.656 ;
    END
  END wd_in_A[39]
  PIN wd_in_B[39]
    DIRECTION INPUT ;
    USE SIGNAL ;
    SHAPE ABUTMENT ;
    PORT
      LAYER M4 ;
      RECT 93.836 265.632 93.860 265.656 ;
    END
  END wd_in_B[39]
  PIN wd_in_A[40]
    DIRECTION INPUT ;
    USE SIGNAL ;
    SHAPE ABUTMENT ;
    PORT
      LAYER M4 ;
      RECT 0.000 267.216 0.024 267.240 ;
    END
  END wd_in_A[40]
  PIN wd_in_B[40]
    DIRECTION INPUT ;
    USE SIGNAL ;
    SHAPE ABUTMENT ;
    PORT
      LAYER M4 ;
      RECT 93.836 267.216 93.860 267.240 ;
    END
  END wd_in_B[40]
  PIN wd_in_A[41]
    DIRECTION INPUT ;
    USE SIGNAL ;
    SHAPE ABUTMENT ;
    PORT
      LAYER M4 ;
      RECT 0.000 268.800 0.024 268.824 ;
    END
  END wd_in_A[41]
  PIN wd_in_B[41]
    DIRECTION INPUT ;
    USE SIGNAL ;
    SHAPE ABUTMENT ;
    PORT
      LAYER M4 ;
      RECT 93.836 268.800 93.860 268.824 ;
    END
  END wd_in_B[41]
  PIN wd_in_A[42]
    DIRECTION INPUT ;
    USE SIGNAL ;
    SHAPE ABUTMENT ;
    PORT
      LAYER M4 ;
      RECT 0.000 270.384 0.024 270.408 ;
    END
  END wd_in_A[42]
  PIN wd_in_B[42]
    DIRECTION INPUT ;
    USE SIGNAL ;
    SHAPE ABUTMENT ;
    PORT
      LAYER M4 ;
      RECT 93.836 270.384 93.860 270.408 ;
    END
  END wd_in_B[42]
  PIN wd_in_A[43]
    DIRECTION INPUT ;
    USE SIGNAL ;
    SHAPE ABUTMENT ;
    PORT
      LAYER M4 ;
      RECT 0.000 271.968 0.024 271.992 ;
    END
  END wd_in_A[43]
  PIN wd_in_B[43]
    DIRECTION INPUT ;
    USE SIGNAL ;
    SHAPE ABUTMENT ;
    PORT
      LAYER M4 ;
      RECT 93.836 271.968 93.860 271.992 ;
    END
  END wd_in_B[43]
  PIN wd_in_A[44]
    DIRECTION INPUT ;
    USE SIGNAL ;
    SHAPE ABUTMENT ;
    PORT
      LAYER M4 ;
      RECT 0.000 273.552 0.024 273.576 ;
    END
  END wd_in_A[44]
  PIN wd_in_B[44]
    DIRECTION INPUT ;
    USE SIGNAL ;
    SHAPE ABUTMENT ;
    PORT
      LAYER M4 ;
      RECT 93.836 273.552 93.860 273.576 ;
    END
  END wd_in_B[44]
  PIN wd_in_A[45]
    DIRECTION INPUT ;
    USE SIGNAL ;
    SHAPE ABUTMENT ;
    PORT
      LAYER M4 ;
      RECT 0.000 275.136 0.024 275.160 ;
    END
  END wd_in_A[45]
  PIN wd_in_B[45]
    DIRECTION INPUT ;
    USE SIGNAL ;
    SHAPE ABUTMENT ;
    PORT
      LAYER M4 ;
      RECT 93.836 275.136 93.860 275.160 ;
    END
  END wd_in_B[45]
  PIN wd_in_A[46]
    DIRECTION INPUT ;
    USE SIGNAL ;
    SHAPE ABUTMENT ;
    PORT
      LAYER M4 ;
      RECT 0.000 276.720 0.024 276.744 ;
    END
  END wd_in_A[46]
  PIN wd_in_B[46]
    DIRECTION INPUT ;
    USE SIGNAL ;
    SHAPE ABUTMENT ;
    PORT
      LAYER M4 ;
      RECT 93.836 276.720 93.860 276.744 ;
    END
  END wd_in_B[46]
  PIN wd_in_A[47]
    DIRECTION INPUT ;
    USE SIGNAL ;
    SHAPE ABUTMENT ;
    PORT
      LAYER M4 ;
      RECT 0.000 278.304 0.024 278.328 ;
    END
  END wd_in_A[47]
  PIN wd_in_B[47]
    DIRECTION INPUT ;
    USE SIGNAL ;
    SHAPE ABUTMENT ;
    PORT
      LAYER M4 ;
      RECT 93.836 278.304 93.860 278.328 ;
    END
  END wd_in_B[47]
  PIN wd_in_A[48]
    DIRECTION INPUT ;
    USE SIGNAL ;
    SHAPE ABUTMENT ;
    PORT
      LAYER M4 ;
      RECT 0.000 279.888 0.024 279.912 ;
    END
  END wd_in_A[48]
  PIN wd_in_B[48]
    DIRECTION INPUT ;
    USE SIGNAL ;
    SHAPE ABUTMENT ;
    PORT
      LAYER M4 ;
      RECT 93.836 279.888 93.860 279.912 ;
    END
  END wd_in_B[48]
  PIN wd_in_A[49]
    DIRECTION INPUT ;
    USE SIGNAL ;
    SHAPE ABUTMENT ;
    PORT
      LAYER M4 ;
      RECT 0.000 281.472 0.024 281.496 ;
    END
  END wd_in_A[49]
  PIN wd_in_B[49]
    DIRECTION INPUT ;
    USE SIGNAL ;
    SHAPE ABUTMENT ;
    PORT
      LAYER M4 ;
      RECT 93.836 281.472 93.860 281.496 ;
    END
  END wd_in_B[49]
  PIN wd_in_A[50]
    DIRECTION INPUT ;
    USE SIGNAL ;
    SHAPE ABUTMENT ;
    PORT
      LAYER M4 ;
      RECT 0.000 283.056 0.024 283.080 ;
    END
  END wd_in_A[50]
  PIN wd_in_B[50]
    DIRECTION INPUT ;
    USE SIGNAL ;
    SHAPE ABUTMENT ;
    PORT
      LAYER M4 ;
      RECT 93.836 283.056 93.860 283.080 ;
    END
  END wd_in_B[50]
  PIN wd_in_A[51]
    DIRECTION INPUT ;
    USE SIGNAL ;
    SHAPE ABUTMENT ;
    PORT
      LAYER M4 ;
      RECT 0.000 284.640 0.024 284.664 ;
    END
  END wd_in_A[51]
  PIN wd_in_B[51]
    DIRECTION INPUT ;
    USE SIGNAL ;
    SHAPE ABUTMENT ;
    PORT
      LAYER M4 ;
      RECT 93.836 284.640 93.860 284.664 ;
    END
  END wd_in_B[51]
  PIN wd_in_A[52]
    DIRECTION INPUT ;
    USE SIGNAL ;
    SHAPE ABUTMENT ;
    PORT
      LAYER M4 ;
      RECT 0.000 286.224 0.024 286.248 ;
    END
  END wd_in_A[52]
  PIN wd_in_B[52]
    DIRECTION INPUT ;
    USE SIGNAL ;
    SHAPE ABUTMENT ;
    PORT
      LAYER M4 ;
      RECT 93.836 286.224 93.860 286.248 ;
    END
  END wd_in_B[52]
  PIN wd_in_A[53]
    DIRECTION INPUT ;
    USE SIGNAL ;
    SHAPE ABUTMENT ;
    PORT
      LAYER M4 ;
      RECT 0.000 287.808 0.024 287.832 ;
    END
  END wd_in_A[53]
  PIN wd_in_B[53]
    DIRECTION INPUT ;
    USE SIGNAL ;
    SHAPE ABUTMENT ;
    PORT
      LAYER M4 ;
      RECT 93.836 287.808 93.860 287.832 ;
    END
  END wd_in_B[53]
  PIN wd_in_A[54]
    DIRECTION INPUT ;
    USE SIGNAL ;
    SHAPE ABUTMENT ;
    PORT
      LAYER M4 ;
      RECT 0.000 289.392 0.024 289.416 ;
    END
  END wd_in_A[54]
  PIN wd_in_B[54]
    DIRECTION INPUT ;
    USE SIGNAL ;
    SHAPE ABUTMENT ;
    PORT
      LAYER M4 ;
      RECT 93.836 289.392 93.860 289.416 ;
    END
  END wd_in_B[54]
  PIN wd_in_A[55]
    DIRECTION INPUT ;
    USE SIGNAL ;
    SHAPE ABUTMENT ;
    PORT
      LAYER M4 ;
      RECT 0.000 290.976 0.024 291.000 ;
    END
  END wd_in_A[55]
  PIN wd_in_B[55]
    DIRECTION INPUT ;
    USE SIGNAL ;
    SHAPE ABUTMENT ;
    PORT
      LAYER M4 ;
      RECT 93.836 290.976 93.860 291.000 ;
    END
  END wd_in_B[55]
  PIN wd_in_A[56]
    DIRECTION INPUT ;
    USE SIGNAL ;
    SHAPE ABUTMENT ;
    PORT
      LAYER M4 ;
      RECT 0.000 292.560 0.024 292.584 ;
    END
  END wd_in_A[56]
  PIN wd_in_B[56]
    DIRECTION INPUT ;
    USE SIGNAL ;
    SHAPE ABUTMENT ;
    PORT
      LAYER M4 ;
      RECT 93.836 292.560 93.860 292.584 ;
    END
  END wd_in_B[56]
  PIN wd_in_A[57]
    DIRECTION INPUT ;
    USE SIGNAL ;
    SHAPE ABUTMENT ;
    PORT
      LAYER M4 ;
      RECT 0.000 294.144 0.024 294.168 ;
    END
  END wd_in_A[57]
  PIN wd_in_B[57]
    DIRECTION INPUT ;
    USE SIGNAL ;
    SHAPE ABUTMENT ;
    PORT
      LAYER M4 ;
      RECT 93.836 294.144 93.860 294.168 ;
    END
  END wd_in_B[57]
  PIN wd_in_A[58]
    DIRECTION INPUT ;
    USE SIGNAL ;
    SHAPE ABUTMENT ;
    PORT
      LAYER M4 ;
      RECT 0.000 295.728 0.024 295.752 ;
    END
  END wd_in_A[58]
  PIN wd_in_B[58]
    DIRECTION INPUT ;
    USE SIGNAL ;
    SHAPE ABUTMENT ;
    PORT
      LAYER M4 ;
      RECT 93.836 295.728 93.860 295.752 ;
    END
  END wd_in_B[58]
  PIN wd_in_A[59]
    DIRECTION INPUT ;
    USE SIGNAL ;
    SHAPE ABUTMENT ;
    PORT
      LAYER M4 ;
      RECT 0.000 297.312 0.024 297.336 ;
    END
  END wd_in_A[59]
  PIN wd_in_B[59]
    DIRECTION INPUT ;
    USE SIGNAL ;
    SHAPE ABUTMENT ;
    PORT
      LAYER M4 ;
      RECT 93.836 297.312 93.860 297.336 ;
    END
  END wd_in_B[59]
  PIN wd_in_A[60]
    DIRECTION INPUT ;
    USE SIGNAL ;
    SHAPE ABUTMENT ;
    PORT
      LAYER M4 ;
      RECT 0.000 298.896 0.024 298.920 ;
    END
  END wd_in_A[60]
  PIN wd_in_B[60]
    DIRECTION INPUT ;
    USE SIGNAL ;
    SHAPE ABUTMENT ;
    PORT
      LAYER M4 ;
      RECT 93.836 298.896 93.860 298.920 ;
    END
  END wd_in_B[60]
  PIN wd_in_A[61]
    DIRECTION INPUT ;
    USE SIGNAL ;
    SHAPE ABUTMENT ;
    PORT
      LAYER M4 ;
      RECT 0.000 300.480 0.024 300.504 ;
    END
  END wd_in_A[61]
  PIN wd_in_B[61]
    DIRECTION INPUT ;
    USE SIGNAL ;
    SHAPE ABUTMENT ;
    PORT
      LAYER M4 ;
      RECT 93.836 300.480 93.860 300.504 ;
    END
  END wd_in_B[61]
  PIN wd_in_A[62]
    DIRECTION INPUT ;
    USE SIGNAL ;
    SHAPE ABUTMENT ;
    PORT
      LAYER M4 ;
      RECT 0.000 302.064 0.024 302.088 ;
    END
  END wd_in_A[62]
  PIN wd_in_B[62]
    DIRECTION INPUT ;
    USE SIGNAL ;
    SHAPE ABUTMENT ;
    PORT
      LAYER M4 ;
      RECT 93.836 302.064 93.860 302.088 ;
    END
  END wd_in_B[62]
  PIN wd_in_A[63]
    DIRECTION INPUT ;
    USE SIGNAL ;
    SHAPE ABUTMENT ;
    PORT
      LAYER M4 ;
      RECT 0.000 303.648 0.024 303.672 ;
    END
  END wd_in_A[63]
  PIN wd_in_B[63]
    DIRECTION INPUT ;
    USE SIGNAL ;
    SHAPE ABUTMENT ;
    PORT
      LAYER M4 ;
      RECT 93.836 303.648 93.860 303.672 ;
    END
  END wd_in_B[63]
  PIN addr_in_A[0]
    DIRECTION INPUT ;
    USE SIGNAL ;
    SHAPE ABUTMENT ;
    PORT
      LAYER M4 ;
      RECT 0.000 305.760 0.024 305.784 ;
    END
  END addr_in_A[0]
  PIN addr_in_B[0]
    DIRECTION INPUT ;
    USE SIGNAL ;
    SHAPE ABUTMENT ;
    PORT
      LAYER M4 ;
      RECT 93.836 305.760 93.860 305.784 ;
    END
  END addr_in_B[0]
  PIN addr_in_A[1]
    DIRECTION INPUT ;
    USE SIGNAL ;
    SHAPE ABUTMENT ;
    PORT
      LAYER M4 ;
      RECT 0.000 307.344 0.024 307.368 ;
    END
  END addr_in_A[1]
  PIN addr_in_B[1]
    DIRECTION INPUT ;
    USE SIGNAL ;
    SHAPE ABUTMENT ;
    PORT
      LAYER M4 ;
      RECT 93.836 307.344 93.860 307.368 ;
    END
  END addr_in_B[1]
  PIN addr_in_A[2]
    DIRECTION INPUT ;
    USE SIGNAL ;
    SHAPE ABUTMENT ;
    PORT
      LAYER M4 ;
      RECT 0.000 308.928 0.024 308.952 ;
    END
  END addr_in_A[2]
  PIN addr_in_B[2]
    DIRECTION INPUT ;
    USE SIGNAL ;
    SHAPE ABUTMENT ;
    PORT
      LAYER M4 ;
      RECT 93.836 308.928 93.860 308.952 ;
    END
  END addr_in_B[2]
  PIN addr_in_A[3]
    DIRECTION INPUT ;
    USE SIGNAL ;
    SHAPE ABUTMENT ;
    PORT
      LAYER M4 ;
      RECT 0.000 310.512 0.024 310.536 ;
    END
  END addr_in_A[3]
  PIN addr_in_B[3]
    DIRECTION INPUT ;
    USE SIGNAL ;
    SHAPE ABUTMENT ;
    PORT
      LAYER M4 ;
      RECT 93.836 310.512 93.860 310.536 ;
    END
  END addr_in_B[3]
  PIN addr_in_A[4]
    DIRECTION INPUT ;
    USE SIGNAL ;
    SHAPE ABUTMENT ;
    PORT
      LAYER M4 ;
      RECT 0.000 312.096 0.024 312.120 ;
    END
  END addr_in_A[4]
  PIN addr_in_B[4]
    DIRECTION INPUT ;
    USE SIGNAL ;
    SHAPE ABUTMENT ;
    PORT
      LAYER M4 ;
      RECT 93.836 312.096 93.860 312.120 ;
    END
  END addr_in_B[4]
  PIN addr_in_A[5]
    DIRECTION INPUT ;
    USE SIGNAL ;
    SHAPE ABUTMENT ;
    PORT
      LAYER M4 ;
      RECT 0.000 313.680 0.024 313.704 ;
    END
  END addr_in_A[5]
  PIN addr_in_B[5]
    DIRECTION INPUT ;
    USE SIGNAL ;
    SHAPE ABUTMENT ;
    PORT
      LAYER M4 ;
      RECT 93.836 313.680 93.860 313.704 ;
    END
  END addr_in_B[5]
  PIN addr_in_A[6]
    DIRECTION INPUT ;
    USE SIGNAL ;
    SHAPE ABUTMENT ;
    PORT
      LAYER M4 ;
      RECT 0.000 315.264 0.024 315.288 ;
    END
  END addr_in_A[6]
  PIN addr_in_B[6]
    DIRECTION INPUT ;
    USE SIGNAL ;
    SHAPE ABUTMENT ;
    PORT
      LAYER M4 ;
      RECT 93.836 315.264 93.860 315.288 ;
    END
  END addr_in_B[6]
  PIN addr_in_A[7]
    DIRECTION INPUT ;
    USE SIGNAL ;
    SHAPE ABUTMENT ;
    PORT
      LAYER M4 ;
      RECT 0.000 316.848 0.024 316.872 ;
    END
  END addr_in_A[7]
  PIN addr_in_B[7]
    DIRECTION INPUT ;
    USE SIGNAL ;
    SHAPE ABUTMENT ;
    PORT
      LAYER M4 ;
      RECT 93.836 316.848 93.860 316.872 ;
    END
  END addr_in_B[7]
  PIN addr_in_A[8]
    DIRECTION INPUT ;
    USE SIGNAL ;
    SHAPE ABUTMENT ;
    PORT
      LAYER M4 ;
      RECT 0.000 318.432 0.024 318.456 ;
    END
  END addr_in_A[8]
  PIN addr_in_B[8]
    DIRECTION INPUT ;
    USE SIGNAL ;
    SHAPE ABUTMENT ;
    PORT
      LAYER M4 ;
      RECT 93.836 318.432 93.860 318.456 ;
    END
  END addr_in_B[8]
  PIN addr_in_A[9]
    DIRECTION INPUT ;
    USE SIGNAL ;
    SHAPE ABUTMENT ;
    PORT
      LAYER M4 ;
      RECT 0.000 320.016 0.024 320.040 ;
    END
  END addr_in_A[9]
  PIN addr_in_B[9]
    DIRECTION INPUT ;
    USE SIGNAL ;
    SHAPE ABUTMENT ;
    PORT
      LAYER M4 ;
      RECT 93.836 320.016 93.860 320.040 ;
    END
  END addr_in_B[9]
  PIN addr_in_A[10]
    DIRECTION INPUT ;
    USE SIGNAL ;
    SHAPE ABUTMENT ;
    PORT
      LAYER M4 ;
      RECT 0.000 321.600 0.024 321.624 ;
    END
  END addr_in_A[10]
  PIN addr_in_B[10]
    DIRECTION INPUT ;
    USE SIGNAL ;
    SHAPE ABUTMENT ;
    PORT
      LAYER M4 ;
      RECT 93.836 321.600 93.860 321.624 ;
    END
  END addr_in_B[10]
  PIN addr_in_A[11]
    DIRECTION INPUT ;
    USE SIGNAL ;
    SHAPE ABUTMENT ;
    PORT
      LAYER M4 ;
      RECT 0.000 323.184 0.024 323.208 ;
    END
  END addr_in_A[11]
  PIN addr_in_B[11]
    DIRECTION INPUT ;
    USE SIGNAL ;
    SHAPE ABUTMENT ;
    PORT
      LAYER M4 ;
      RECT 93.836 323.184 93.860 323.208 ;
    END
  END addr_in_B[11]
  PIN addr_in_A[12]
    DIRECTION INPUT ;
    USE SIGNAL ;
    SHAPE ABUTMENT ;
    PORT
      LAYER M4 ;
      RECT 0.000 324.768 0.024 324.792 ;
    END
  END addr_in_A[12]
  PIN addr_in_B[12]
    DIRECTION INPUT ;
    USE SIGNAL ;
    SHAPE ABUTMENT ;
    PORT
      LAYER M4 ;
      RECT 93.836 324.768 93.860 324.792 ;
    END
  END addr_in_B[12]
  PIN we_in_A
    DIRECTION INPUT ;
    USE SIGNAL ;
    SHAPE ABUTMENT ;
    PORT
      LAYER M4 ;
      RECT 0.000 326.880 0.024 326.904 ;
    END
  END we_in_A
  PIN we_in_B
    DIRECTION INPUT ;
    USE SIGNAL ;
    SHAPE ABUTMENT ;
    PORT
      LAYER M4 ;
      RECT 93.836 326.880 93.860 326.904 ;
    END
  END we_in_B
  PIN ce_in
    DIRECTION INPUT ;
    USE SIGNAL ;
    SHAPE ABUTMENT ;
    PORT
      LAYER M4 ;
      RECT 0.000 328.464 0.024 328.488 ;
    END
  END ce_in
  PIN clk
    DIRECTION INPUT ;
    USE SIGNAL ;
    SHAPE ABUTMENT ;
    PORT
      LAYER M4 ;
      RECT 0.000 330.048 0.024 330.072 ;
    END
  END clk
  PIN VSS
    DIRECTION INOUT ;
    USE GROUND ;
    PORT
      LAYER M4 ;
      RECT 0.048 0.000 93.812 0.096 ;
      RECT 0.048 0.768 93.812 0.864 ;
      RECT 0.048 1.536 93.812 1.632 ;
      RECT 0.048 2.304 93.812 2.400 ;
      RECT 0.048 3.072 93.812 3.168 ;
      RECT 0.048 3.840 93.812 3.936 ;
      RECT 0.048 4.608 93.812 4.704 ;
      RECT 0.048 5.376 93.812 5.472 ;
      RECT 0.048 6.144 93.812 6.240 ;
      RECT 0.048 6.912 93.812 7.008 ;
      RECT 0.048 7.680 93.812 7.776 ;
      RECT 0.048 8.448 93.812 8.544 ;
      RECT 0.048 9.216 93.812 9.312 ;
      RECT 0.048 9.984 93.812 10.080 ;
      RECT 0.048 10.752 93.812 10.848 ;
      RECT 0.048 11.520 93.812 11.616 ;
      RECT 0.048 12.288 93.812 12.384 ;
      RECT 0.048 13.056 93.812 13.152 ;
      RECT 0.048 13.824 93.812 13.920 ;
      RECT 0.048 14.592 93.812 14.688 ;
      RECT 0.048 15.360 93.812 15.456 ;
      RECT 0.048 16.128 93.812 16.224 ;
      RECT 0.048 16.896 93.812 16.992 ;
      RECT 0.048 17.664 93.812 17.760 ;
      RECT 0.048 18.432 93.812 18.528 ;
      RECT 0.048 19.200 93.812 19.296 ;
      RECT 0.048 19.968 93.812 20.064 ;
      RECT 0.048 20.736 93.812 20.832 ;
      RECT 0.048 21.504 93.812 21.600 ;
      RECT 0.048 22.272 93.812 22.368 ;
      RECT 0.048 23.040 93.812 23.136 ;
      RECT 0.048 23.808 93.812 23.904 ;
      RECT 0.048 24.576 93.812 24.672 ;
      RECT 0.048 25.344 93.812 25.440 ;
      RECT 0.048 26.112 93.812 26.208 ;
      RECT 0.048 26.880 93.812 26.976 ;
      RECT 0.048 27.648 93.812 27.744 ;
      RECT 0.048 28.416 93.812 28.512 ;
      RECT 0.048 29.184 93.812 29.280 ;
      RECT 0.048 29.952 93.812 30.048 ;
      RECT 0.048 30.720 93.812 30.816 ;
      RECT 0.048 31.488 93.812 31.584 ;
      RECT 0.048 32.256 93.812 32.352 ;
      RECT 0.048 33.024 93.812 33.120 ;
      RECT 0.048 33.792 93.812 33.888 ;
      RECT 0.048 34.560 93.812 34.656 ;
      RECT 0.048 35.328 93.812 35.424 ;
      RECT 0.048 36.096 93.812 36.192 ;
      RECT 0.048 36.864 93.812 36.960 ;
      RECT 0.048 37.632 93.812 37.728 ;
      RECT 0.048 38.400 93.812 38.496 ;
      RECT 0.048 39.168 93.812 39.264 ;
      RECT 0.048 39.936 93.812 40.032 ;
      RECT 0.048 40.704 93.812 40.800 ;
      RECT 0.048 41.472 93.812 41.568 ;
      RECT 0.048 42.240 93.812 42.336 ;
      RECT 0.048 43.008 93.812 43.104 ;
      RECT 0.048 43.776 93.812 43.872 ;
      RECT 0.048 44.544 93.812 44.640 ;
      RECT 0.048 45.312 93.812 45.408 ;
      RECT 0.048 46.080 93.812 46.176 ;
      RECT 0.048 46.848 93.812 46.944 ;
      RECT 0.048 47.616 93.812 47.712 ;
      RECT 0.048 48.384 93.812 48.480 ;
      RECT 0.048 49.152 93.812 49.248 ;
      RECT 0.048 49.920 93.812 50.016 ;
      RECT 0.048 50.688 93.812 50.784 ;
      RECT 0.048 51.456 93.812 51.552 ;
      RECT 0.048 52.224 93.812 52.320 ;
      RECT 0.048 52.992 93.812 53.088 ;
      RECT 0.048 53.760 93.812 53.856 ;
      RECT 0.048 54.528 93.812 54.624 ;
      RECT 0.048 55.296 93.812 55.392 ;
      RECT 0.048 56.064 93.812 56.160 ;
      RECT 0.048 56.832 93.812 56.928 ;
      RECT 0.048 57.600 93.812 57.696 ;
      RECT 0.048 58.368 93.812 58.464 ;
      RECT 0.048 59.136 93.812 59.232 ;
      RECT 0.048 59.904 93.812 60.000 ;
      RECT 0.048 60.672 93.812 60.768 ;
      RECT 0.048 61.440 93.812 61.536 ;
      RECT 0.048 62.208 93.812 62.304 ;
      RECT 0.048 62.976 93.812 63.072 ;
      RECT 0.048 63.744 93.812 63.840 ;
      RECT 0.048 64.512 93.812 64.608 ;
      RECT 0.048 65.280 93.812 65.376 ;
      RECT 0.048 66.048 93.812 66.144 ;
      RECT 0.048 66.816 93.812 66.912 ;
      RECT 0.048 67.584 93.812 67.680 ;
      RECT 0.048 68.352 93.812 68.448 ;
      RECT 0.048 69.120 93.812 69.216 ;
      RECT 0.048 69.888 93.812 69.984 ;
      RECT 0.048 70.656 93.812 70.752 ;
      RECT 0.048 71.424 93.812 71.520 ;
      RECT 0.048 72.192 93.812 72.288 ;
      RECT 0.048 72.960 93.812 73.056 ;
      RECT 0.048 73.728 93.812 73.824 ;
      RECT 0.048 74.496 93.812 74.592 ;
      RECT 0.048 75.264 93.812 75.360 ;
      RECT 0.048 76.032 93.812 76.128 ;
      RECT 0.048 76.800 93.812 76.896 ;
      RECT 0.048 77.568 93.812 77.664 ;
      RECT 0.048 78.336 93.812 78.432 ;
      RECT 0.048 79.104 93.812 79.200 ;
      RECT 0.048 79.872 93.812 79.968 ;
      RECT 0.048 80.640 93.812 80.736 ;
      RECT 0.048 81.408 93.812 81.504 ;
      RECT 0.048 82.176 93.812 82.272 ;
      RECT 0.048 82.944 93.812 83.040 ;
      RECT 0.048 83.712 93.812 83.808 ;
      RECT 0.048 84.480 93.812 84.576 ;
      RECT 0.048 85.248 93.812 85.344 ;
      RECT 0.048 86.016 93.812 86.112 ;
      RECT 0.048 86.784 93.812 86.880 ;
      RECT 0.048 87.552 93.812 87.648 ;
      RECT 0.048 88.320 93.812 88.416 ;
      RECT 0.048 89.088 93.812 89.184 ;
      RECT 0.048 89.856 93.812 89.952 ;
      RECT 0.048 90.624 93.812 90.720 ;
      RECT 0.048 91.392 93.812 91.488 ;
      RECT 0.048 92.160 93.812 92.256 ;
      RECT 0.048 92.928 93.812 93.024 ;
      RECT 0.048 93.696 93.812 93.792 ;
      RECT 0.048 94.464 93.812 94.560 ;
      RECT 0.048 95.232 93.812 95.328 ;
      RECT 0.048 96.000 93.812 96.096 ;
      RECT 0.048 96.768 93.812 96.864 ;
      RECT 0.048 97.536 93.812 97.632 ;
      RECT 0.048 98.304 93.812 98.400 ;
      RECT 0.048 99.072 93.812 99.168 ;
      RECT 0.048 99.840 93.812 99.936 ;
      RECT 0.048 100.608 93.812 100.704 ;
      RECT 0.048 101.376 93.812 101.472 ;
      RECT 0.048 102.144 93.812 102.240 ;
      RECT 0.048 102.912 93.812 103.008 ;
      RECT 0.048 103.680 93.812 103.776 ;
      RECT 0.048 104.448 93.812 104.544 ;
      RECT 0.048 105.216 93.812 105.312 ;
      RECT 0.048 105.984 93.812 106.080 ;
      RECT 0.048 106.752 93.812 106.848 ;
      RECT 0.048 107.520 93.812 107.616 ;
      RECT 0.048 108.288 93.812 108.384 ;
      RECT 0.048 109.056 93.812 109.152 ;
      RECT 0.048 109.824 93.812 109.920 ;
      RECT 0.048 110.592 93.812 110.688 ;
      RECT 0.048 111.360 93.812 111.456 ;
      RECT 0.048 112.128 93.812 112.224 ;
      RECT 0.048 112.896 93.812 112.992 ;
      RECT 0.048 113.664 93.812 113.760 ;
      RECT 0.048 114.432 93.812 114.528 ;
      RECT 0.048 115.200 93.812 115.296 ;
      RECT 0.048 115.968 93.812 116.064 ;
      RECT 0.048 116.736 93.812 116.832 ;
      RECT 0.048 117.504 93.812 117.600 ;
      RECT 0.048 118.272 93.812 118.368 ;
      RECT 0.048 119.040 93.812 119.136 ;
      RECT 0.048 119.808 93.812 119.904 ;
      RECT 0.048 120.576 93.812 120.672 ;
      RECT 0.048 121.344 93.812 121.440 ;
      RECT 0.048 122.112 93.812 122.208 ;
      RECT 0.048 122.880 93.812 122.976 ;
      RECT 0.048 123.648 93.812 123.744 ;
      RECT 0.048 124.416 93.812 124.512 ;
      RECT 0.048 125.184 93.812 125.280 ;
      RECT 0.048 125.952 93.812 126.048 ;
      RECT 0.048 126.720 93.812 126.816 ;
      RECT 0.048 127.488 93.812 127.584 ;
      RECT 0.048 128.256 93.812 128.352 ;
      RECT 0.048 129.024 93.812 129.120 ;
      RECT 0.048 129.792 93.812 129.888 ;
      RECT 0.048 130.560 93.812 130.656 ;
      RECT 0.048 131.328 93.812 131.424 ;
      RECT 0.048 132.096 93.812 132.192 ;
      RECT 0.048 132.864 93.812 132.960 ;
      RECT 0.048 133.632 93.812 133.728 ;
      RECT 0.048 134.400 93.812 134.496 ;
      RECT 0.048 135.168 93.812 135.264 ;
      RECT 0.048 135.936 93.812 136.032 ;
      RECT 0.048 136.704 93.812 136.800 ;
      RECT 0.048 137.472 93.812 137.568 ;
      RECT 0.048 138.240 93.812 138.336 ;
      RECT 0.048 139.008 93.812 139.104 ;
      RECT 0.048 139.776 93.812 139.872 ;
      RECT 0.048 140.544 93.812 140.640 ;
      RECT 0.048 141.312 93.812 141.408 ;
      RECT 0.048 142.080 93.812 142.176 ;
      RECT 0.048 142.848 93.812 142.944 ;
      RECT 0.048 143.616 93.812 143.712 ;
      RECT 0.048 144.384 93.812 144.480 ;
      RECT 0.048 145.152 93.812 145.248 ;
      RECT 0.048 145.920 93.812 146.016 ;
      RECT 0.048 146.688 93.812 146.784 ;
      RECT 0.048 147.456 93.812 147.552 ;
      RECT 0.048 148.224 93.812 148.320 ;
      RECT 0.048 148.992 93.812 149.088 ;
      RECT 0.048 149.760 93.812 149.856 ;
      RECT 0.048 150.528 93.812 150.624 ;
      RECT 0.048 151.296 93.812 151.392 ;
      RECT 0.048 152.064 93.812 152.160 ;
      RECT 0.048 152.832 93.812 152.928 ;
      RECT 0.048 153.600 93.812 153.696 ;
      RECT 0.048 154.368 93.812 154.464 ;
      RECT 0.048 155.136 93.812 155.232 ;
      RECT 0.048 155.904 93.812 156.000 ;
      RECT 0.048 156.672 93.812 156.768 ;
      RECT 0.048 157.440 93.812 157.536 ;
      RECT 0.048 158.208 93.812 158.304 ;
      RECT 0.048 158.976 93.812 159.072 ;
      RECT 0.048 159.744 93.812 159.840 ;
      RECT 0.048 160.512 93.812 160.608 ;
      RECT 0.048 161.280 93.812 161.376 ;
      RECT 0.048 162.048 93.812 162.144 ;
      RECT 0.048 162.816 93.812 162.912 ;
      RECT 0.048 163.584 93.812 163.680 ;
      RECT 0.048 164.352 93.812 164.448 ;
      RECT 0.048 165.120 93.812 165.216 ;
      RECT 0.048 165.888 93.812 165.984 ;
      RECT 0.048 166.656 93.812 166.752 ;
      RECT 0.048 167.424 93.812 167.520 ;
      RECT 0.048 168.192 93.812 168.288 ;
      RECT 0.048 168.960 93.812 169.056 ;
      RECT 0.048 169.728 93.812 169.824 ;
      RECT 0.048 170.496 93.812 170.592 ;
      RECT 0.048 171.264 93.812 171.360 ;
      RECT 0.048 172.032 93.812 172.128 ;
      RECT 0.048 172.800 93.812 172.896 ;
      RECT 0.048 173.568 93.812 173.664 ;
      RECT 0.048 174.336 93.812 174.432 ;
      RECT 0.048 175.104 93.812 175.200 ;
      RECT 0.048 175.872 93.812 175.968 ;
      RECT 0.048 176.640 93.812 176.736 ;
      RECT 0.048 177.408 93.812 177.504 ;
      RECT 0.048 178.176 93.812 178.272 ;
      RECT 0.048 178.944 93.812 179.040 ;
      RECT 0.048 179.712 93.812 179.808 ;
      RECT 0.048 180.480 93.812 180.576 ;
      RECT 0.048 181.248 93.812 181.344 ;
      RECT 0.048 182.016 93.812 182.112 ;
      RECT 0.048 182.784 93.812 182.880 ;
      RECT 0.048 183.552 93.812 183.648 ;
      RECT 0.048 184.320 93.812 184.416 ;
      RECT 0.048 185.088 93.812 185.184 ;
      RECT 0.048 185.856 93.812 185.952 ;
      RECT 0.048 186.624 93.812 186.720 ;
      RECT 0.048 187.392 93.812 187.488 ;
      RECT 0.048 188.160 93.812 188.256 ;
      RECT 0.048 188.928 93.812 189.024 ;
      RECT 0.048 189.696 93.812 189.792 ;
      RECT 0.048 190.464 93.812 190.560 ;
      RECT 0.048 191.232 93.812 191.328 ;
      RECT 0.048 192.000 93.812 192.096 ;
      RECT 0.048 192.768 93.812 192.864 ;
      RECT 0.048 193.536 93.812 193.632 ;
      RECT 0.048 194.304 93.812 194.400 ;
      RECT 0.048 195.072 93.812 195.168 ;
      RECT 0.048 195.840 93.812 195.936 ;
      RECT 0.048 196.608 93.812 196.704 ;
      RECT 0.048 197.376 93.812 197.472 ;
      RECT 0.048 198.144 93.812 198.240 ;
      RECT 0.048 198.912 93.812 199.008 ;
      RECT 0.048 199.680 93.812 199.776 ;
      RECT 0.048 200.448 93.812 200.544 ;
      RECT 0.048 201.216 93.812 201.312 ;
      RECT 0.048 201.984 93.812 202.080 ;
      RECT 0.048 202.752 93.812 202.848 ;
      RECT 0.048 203.520 93.812 203.616 ;
      RECT 0.048 204.288 93.812 204.384 ;
      RECT 0.048 205.056 93.812 205.152 ;
      RECT 0.048 205.824 93.812 205.920 ;
      RECT 0.048 206.592 93.812 206.688 ;
      RECT 0.048 207.360 93.812 207.456 ;
      RECT 0.048 208.128 93.812 208.224 ;
      RECT 0.048 208.896 93.812 208.992 ;
      RECT 0.048 209.664 93.812 209.760 ;
      RECT 0.048 210.432 93.812 210.528 ;
      RECT 0.048 211.200 93.812 211.296 ;
      RECT 0.048 211.968 93.812 212.064 ;
      RECT 0.048 212.736 93.812 212.832 ;
      RECT 0.048 213.504 93.812 213.600 ;
      RECT 0.048 214.272 93.812 214.368 ;
      RECT 0.048 215.040 93.812 215.136 ;
      RECT 0.048 215.808 93.812 215.904 ;
      RECT 0.048 216.576 93.812 216.672 ;
      RECT 0.048 217.344 93.812 217.440 ;
      RECT 0.048 218.112 93.812 218.208 ;
      RECT 0.048 218.880 93.812 218.976 ;
      RECT 0.048 219.648 93.812 219.744 ;
      RECT 0.048 220.416 93.812 220.512 ;
      RECT 0.048 221.184 93.812 221.280 ;
      RECT 0.048 221.952 93.812 222.048 ;
      RECT 0.048 222.720 93.812 222.816 ;
      RECT 0.048 223.488 93.812 223.584 ;
      RECT 0.048 224.256 93.812 224.352 ;
      RECT 0.048 225.024 93.812 225.120 ;
      RECT 0.048 225.792 93.812 225.888 ;
      RECT 0.048 226.560 93.812 226.656 ;
      RECT 0.048 227.328 93.812 227.424 ;
      RECT 0.048 228.096 93.812 228.192 ;
      RECT 0.048 228.864 93.812 228.960 ;
      RECT 0.048 229.632 93.812 229.728 ;
      RECT 0.048 230.400 93.812 230.496 ;
      RECT 0.048 231.168 93.812 231.264 ;
      RECT 0.048 231.936 93.812 232.032 ;
      RECT 0.048 232.704 93.812 232.800 ;
      RECT 0.048 233.472 93.812 233.568 ;
      RECT 0.048 234.240 93.812 234.336 ;
      RECT 0.048 235.008 93.812 235.104 ;
      RECT 0.048 235.776 93.812 235.872 ;
      RECT 0.048 236.544 93.812 236.640 ;
      RECT 0.048 237.312 93.812 237.408 ;
      RECT 0.048 238.080 93.812 238.176 ;
      RECT 0.048 238.848 93.812 238.944 ;
      RECT 0.048 239.616 93.812 239.712 ;
      RECT 0.048 240.384 93.812 240.480 ;
      RECT 0.048 241.152 93.812 241.248 ;
      RECT 0.048 241.920 93.812 242.016 ;
      RECT 0.048 242.688 93.812 242.784 ;
      RECT 0.048 243.456 93.812 243.552 ;
      RECT 0.048 244.224 93.812 244.320 ;
      RECT 0.048 244.992 93.812 245.088 ;
      RECT 0.048 245.760 93.812 245.856 ;
      RECT 0.048 246.528 93.812 246.624 ;
      RECT 0.048 247.296 93.812 247.392 ;
      RECT 0.048 248.064 93.812 248.160 ;
      RECT 0.048 248.832 93.812 248.928 ;
      RECT 0.048 249.600 93.812 249.696 ;
      RECT 0.048 250.368 93.812 250.464 ;
      RECT 0.048 251.136 93.812 251.232 ;
      RECT 0.048 251.904 93.812 252.000 ;
      RECT 0.048 252.672 93.812 252.768 ;
      RECT 0.048 253.440 93.812 253.536 ;
      RECT 0.048 254.208 93.812 254.304 ;
      RECT 0.048 254.976 93.812 255.072 ;
      RECT 0.048 255.744 93.812 255.840 ;
      RECT 0.048 256.512 93.812 256.608 ;
      RECT 0.048 257.280 93.812 257.376 ;
      RECT 0.048 258.048 93.812 258.144 ;
      RECT 0.048 258.816 93.812 258.912 ;
      RECT 0.048 259.584 93.812 259.680 ;
      RECT 0.048 260.352 93.812 260.448 ;
      RECT 0.048 261.120 93.812 261.216 ;
      RECT 0.048 261.888 93.812 261.984 ;
      RECT 0.048 262.656 93.812 262.752 ;
      RECT 0.048 263.424 93.812 263.520 ;
      RECT 0.048 264.192 93.812 264.288 ;
      RECT 0.048 264.960 93.812 265.056 ;
      RECT 0.048 265.728 93.812 265.824 ;
      RECT 0.048 266.496 93.812 266.592 ;
      RECT 0.048 267.264 93.812 267.360 ;
      RECT 0.048 268.032 93.812 268.128 ;
      RECT 0.048 268.800 93.812 268.896 ;
      RECT 0.048 269.568 93.812 269.664 ;
      RECT 0.048 270.336 93.812 270.432 ;
      RECT 0.048 271.104 93.812 271.200 ;
      RECT 0.048 271.872 93.812 271.968 ;
      RECT 0.048 272.640 93.812 272.736 ;
      RECT 0.048 273.408 93.812 273.504 ;
      RECT 0.048 274.176 93.812 274.272 ;
      RECT 0.048 274.944 93.812 275.040 ;
      RECT 0.048 275.712 93.812 275.808 ;
      RECT 0.048 276.480 93.812 276.576 ;
      RECT 0.048 277.248 93.812 277.344 ;
      RECT 0.048 278.016 93.812 278.112 ;
      RECT 0.048 278.784 93.812 278.880 ;
      RECT 0.048 279.552 93.812 279.648 ;
      RECT 0.048 280.320 93.812 280.416 ;
      RECT 0.048 281.088 93.812 281.184 ;
      RECT 0.048 281.856 93.812 281.952 ;
      RECT 0.048 282.624 93.812 282.720 ;
      RECT 0.048 283.392 93.812 283.488 ;
      RECT 0.048 284.160 93.812 284.256 ;
      RECT 0.048 284.928 93.812 285.024 ;
      RECT 0.048 285.696 93.812 285.792 ;
      RECT 0.048 286.464 93.812 286.560 ;
      RECT 0.048 287.232 93.812 287.328 ;
      RECT 0.048 288.000 93.812 288.096 ;
      RECT 0.048 288.768 93.812 288.864 ;
      RECT 0.048 289.536 93.812 289.632 ;
      RECT 0.048 290.304 93.812 290.400 ;
      RECT 0.048 291.072 93.812 291.168 ;
      RECT 0.048 291.840 93.812 291.936 ;
      RECT 0.048 292.608 93.812 292.704 ;
      RECT 0.048 293.376 93.812 293.472 ;
      RECT 0.048 294.144 93.812 294.240 ;
      RECT 0.048 294.912 93.812 295.008 ;
      RECT 0.048 295.680 93.812 295.776 ;
      RECT 0.048 296.448 93.812 296.544 ;
      RECT 0.048 297.216 93.812 297.312 ;
      RECT 0.048 297.984 93.812 298.080 ;
      RECT 0.048 298.752 93.812 298.848 ;
      RECT 0.048 299.520 93.812 299.616 ;
      RECT 0.048 300.288 93.812 300.384 ;
      RECT 0.048 301.056 93.812 301.152 ;
      RECT 0.048 301.824 93.812 301.920 ;
      RECT 0.048 302.592 93.812 302.688 ;
      RECT 0.048 303.360 93.812 303.456 ;
      RECT 0.048 304.128 93.812 304.224 ;
      RECT 0.048 304.896 93.812 304.992 ;
      RECT 0.048 305.664 93.812 305.760 ;
      RECT 0.048 306.432 93.812 306.528 ;
      RECT 0.048 307.200 93.812 307.296 ;
      RECT 0.048 307.968 93.812 308.064 ;
      RECT 0.048 308.736 93.812 308.832 ;
      RECT 0.048 309.504 93.812 309.600 ;
      RECT 0.048 310.272 93.812 310.368 ;
      RECT 0.048 311.040 93.812 311.136 ;
      RECT 0.048 311.808 93.812 311.904 ;
      RECT 0.048 312.576 93.812 312.672 ;
      RECT 0.048 313.344 93.812 313.440 ;
      RECT 0.048 314.112 93.812 314.208 ;
      RECT 0.048 314.880 93.812 314.976 ;
      RECT 0.048 315.648 93.812 315.744 ;
      RECT 0.048 316.416 93.812 316.512 ;
      RECT 0.048 317.184 93.812 317.280 ;
      RECT 0.048 317.952 93.812 318.048 ;
      RECT 0.048 318.720 93.812 318.816 ;
      RECT 0.048 319.488 93.812 319.584 ;
      RECT 0.048 320.256 93.812 320.352 ;
      RECT 0.048 321.024 93.812 321.120 ;
      RECT 0.048 321.792 93.812 321.888 ;
      RECT 0.048 322.560 93.812 322.656 ;
      RECT 0.048 323.328 93.812 323.424 ;
      RECT 0.048 324.096 93.812 324.192 ;
      RECT 0.048 324.864 93.812 324.960 ;
      RECT 0.048 325.632 93.812 325.728 ;
      RECT 0.048 326.400 93.812 326.496 ;
      RECT 0.048 327.168 93.812 327.264 ;
      RECT 0.048 327.936 93.812 328.032 ;
      RECT 0.048 328.704 93.812 328.800 ;
      RECT 0.048 329.472 93.812 329.568 ;
      RECT 0.048 330.240 93.812 330.336 ;
      RECT 0.048 331.008 93.812 331.104 ;
    END
  END VSS
  PIN VDD
    DIRECTION INOUT ;
    USE POWER ;
    PORT
      LAYER M4 ;
      RECT 0.048 0.384 93.812 0.480 ;
      RECT 0.048 1.152 93.812 1.248 ;
      RECT 0.048 1.920 93.812 2.016 ;
      RECT 0.048 2.688 93.812 2.784 ;
      RECT 0.048 3.456 93.812 3.552 ;
      RECT 0.048 4.224 93.812 4.320 ;
      RECT 0.048 4.992 93.812 5.088 ;
      RECT 0.048 5.760 93.812 5.856 ;
      RECT 0.048 6.528 93.812 6.624 ;
      RECT 0.048 7.296 93.812 7.392 ;
      RECT 0.048 8.064 93.812 8.160 ;
      RECT 0.048 8.832 93.812 8.928 ;
      RECT 0.048 9.600 93.812 9.696 ;
      RECT 0.048 10.368 93.812 10.464 ;
      RECT 0.048 11.136 93.812 11.232 ;
      RECT 0.048 11.904 93.812 12.000 ;
      RECT 0.048 12.672 93.812 12.768 ;
      RECT 0.048 13.440 93.812 13.536 ;
      RECT 0.048 14.208 93.812 14.304 ;
      RECT 0.048 14.976 93.812 15.072 ;
      RECT 0.048 15.744 93.812 15.840 ;
      RECT 0.048 16.512 93.812 16.608 ;
      RECT 0.048 17.280 93.812 17.376 ;
      RECT 0.048 18.048 93.812 18.144 ;
      RECT 0.048 18.816 93.812 18.912 ;
      RECT 0.048 19.584 93.812 19.680 ;
      RECT 0.048 20.352 93.812 20.448 ;
      RECT 0.048 21.120 93.812 21.216 ;
      RECT 0.048 21.888 93.812 21.984 ;
      RECT 0.048 22.656 93.812 22.752 ;
      RECT 0.048 23.424 93.812 23.520 ;
      RECT 0.048 24.192 93.812 24.288 ;
      RECT 0.048 24.960 93.812 25.056 ;
      RECT 0.048 25.728 93.812 25.824 ;
      RECT 0.048 26.496 93.812 26.592 ;
      RECT 0.048 27.264 93.812 27.360 ;
      RECT 0.048 28.032 93.812 28.128 ;
      RECT 0.048 28.800 93.812 28.896 ;
      RECT 0.048 29.568 93.812 29.664 ;
      RECT 0.048 30.336 93.812 30.432 ;
      RECT 0.048 31.104 93.812 31.200 ;
      RECT 0.048 31.872 93.812 31.968 ;
      RECT 0.048 32.640 93.812 32.736 ;
      RECT 0.048 33.408 93.812 33.504 ;
      RECT 0.048 34.176 93.812 34.272 ;
      RECT 0.048 34.944 93.812 35.040 ;
      RECT 0.048 35.712 93.812 35.808 ;
      RECT 0.048 36.480 93.812 36.576 ;
      RECT 0.048 37.248 93.812 37.344 ;
      RECT 0.048 38.016 93.812 38.112 ;
      RECT 0.048 38.784 93.812 38.880 ;
      RECT 0.048 39.552 93.812 39.648 ;
      RECT 0.048 40.320 93.812 40.416 ;
      RECT 0.048 41.088 93.812 41.184 ;
      RECT 0.048 41.856 93.812 41.952 ;
      RECT 0.048 42.624 93.812 42.720 ;
      RECT 0.048 43.392 93.812 43.488 ;
      RECT 0.048 44.160 93.812 44.256 ;
      RECT 0.048 44.928 93.812 45.024 ;
      RECT 0.048 45.696 93.812 45.792 ;
      RECT 0.048 46.464 93.812 46.560 ;
      RECT 0.048 47.232 93.812 47.328 ;
      RECT 0.048 48.000 93.812 48.096 ;
      RECT 0.048 48.768 93.812 48.864 ;
      RECT 0.048 49.536 93.812 49.632 ;
      RECT 0.048 50.304 93.812 50.400 ;
      RECT 0.048 51.072 93.812 51.168 ;
      RECT 0.048 51.840 93.812 51.936 ;
      RECT 0.048 52.608 93.812 52.704 ;
      RECT 0.048 53.376 93.812 53.472 ;
      RECT 0.048 54.144 93.812 54.240 ;
      RECT 0.048 54.912 93.812 55.008 ;
      RECT 0.048 55.680 93.812 55.776 ;
      RECT 0.048 56.448 93.812 56.544 ;
      RECT 0.048 57.216 93.812 57.312 ;
      RECT 0.048 57.984 93.812 58.080 ;
      RECT 0.048 58.752 93.812 58.848 ;
      RECT 0.048 59.520 93.812 59.616 ;
      RECT 0.048 60.288 93.812 60.384 ;
      RECT 0.048 61.056 93.812 61.152 ;
      RECT 0.048 61.824 93.812 61.920 ;
      RECT 0.048 62.592 93.812 62.688 ;
      RECT 0.048 63.360 93.812 63.456 ;
      RECT 0.048 64.128 93.812 64.224 ;
      RECT 0.048 64.896 93.812 64.992 ;
      RECT 0.048 65.664 93.812 65.760 ;
      RECT 0.048 66.432 93.812 66.528 ;
      RECT 0.048 67.200 93.812 67.296 ;
      RECT 0.048 67.968 93.812 68.064 ;
      RECT 0.048 68.736 93.812 68.832 ;
      RECT 0.048 69.504 93.812 69.600 ;
      RECT 0.048 70.272 93.812 70.368 ;
      RECT 0.048 71.040 93.812 71.136 ;
      RECT 0.048 71.808 93.812 71.904 ;
      RECT 0.048 72.576 93.812 72.672 ;
      RECT 0.048 73.344 93.812 73.440 ;
      RECT 0.048 74.112 93.812 74.208 ;
      RECT 0.048 74.880 93.812 74.976 ;
      RECT 0.048 75.648 93.812 75.744 ;
      RECT 0.048 76.416 93.812 76.512 ;
      RECT 0.048 77.184 93.812 77.280 ;
      RECT 0.048 77.952 93.812 78.048 ;
      RECT 0.048 78.720 93.812 78.816 ;
      RECT 0.048 79.488 93.812 79.584 ;
      RECT 0.048 80.256 93.812 80.352 ;
      RECT 0.048 81.024 93.812 81.120 ;
      RECT 0.048 81.792 93.812 81.888 ;
      RECT 0.048 82.560 93.812 82.656 ;
      RECT 0.048 83.328 93.812 83.424 ;
      RECT 0.048 84.096 93.812 84.192 ;
      RECT 0.048 84.864 93.812 84.960 ;
      RECT 0.048 85.632 93.812 85.728 ;
      RECT 0.048 86.400 93.812 86.496 ;
      RECT 0.048 87.168 93.812 87.264 ;
      RECT 0.048 87.936 93.812 88.032 ;
      RECT 0.048 88.704 93.812 88.800 ;
      RECT 0.048 89.472 93.812 89.568 ;
      RECT 0.048 90.240 93.812 90.336 ;
      RECT 0.048 91.008 93.812 91.104 ;
      RECT 0.048 91.776 93.812 91.872 ;
      RECT 0.048 92.544 93.812 92.640 ;
      RECT 0.048 93.312 93.812 93.408 ;
      RECT 0.048 94.080 93.812 94.176 ;
      RECT 0.048 94.848 93.812 94.944 ;
      RECT 0.048 95.616 93.812 95.712 ;
      RECT 0.048 96.384 93.812 96.480 ;
      RECT 0.048 97.152 93.812 97.248 ;
      RECT 0.048 97.920 93.812 98.016 ;
      RECT 0.048 98.688 93.812 98.784 ;
      RECT 0.048 99.456 93.812 99.552 ;
      RECT 0.048 100.224 93.812 100.320 ;
      RECT 0.048 100.992 93.812 101.088 ;
      RECT 0.048 101.760 93.812 101.856 ;
      RECT 0.048 102.528 93.812 102.624 ;
      RECT 0.048 103.296 93.812 103.392 ;
      RECT 0.048 104.064 93.812 104.160 ;
      RECT 0.048 104.832 93.812 104.928 ;
      RECT 0.048 105.600 93.812 105.696 ;
      RECT 0.048 106.368 93.812 106.464 ;
      RECT 0.048 107.136 93.812 107.232 ;
      RECT 0.048 107.904 93.812 108.000 ;
      RECT 0.048 108.672 93.812 108.768 ;
      RECT 0.048 109.440 93.812 109.536 ;
      RECT 0.048 110.208 93.812 110.304 ;
      RECT 0.048 110.976 93.812 111.072 ;
      RECT 0.048 111.744 93.812 111.840 ;
      RECT 0.048 112.512 93.812 112.608 ;
      RECT 0.048 113.280 93.812 113.376 ;
      RECT 0.048 114.048 93.812 114.144 ;
      RECT 0.048 114.816 93.812 114.912 ;
      RECT 0.048 115.584 93.812 115.680 ;
      RECT 0.048 116.352 93.812 116.448 ;
      RECT 0.048 117.120 93.812 117.216 ;
      RECT 0.048 117.888 93.812 117.984 ;
      RECT 0.048 118.656 93.812 118.752 ;
      RECT 0.048 119.424 93.812 119.520 ;
      RECT 0.048 120.192 93.812 120.288 ;
      RECT 0.048 120.960 93.812 121.056 ;
      RECT 0.048 121.728 93.812 121.824 ;
      RECT 0.048 122.496 93.812 122.592 ;
      RECT 0.048 123.264 93.812 123.360 ;
      RECT 0.048 124.032 93.812 124.128 ;
      RECT 0.048 124.800 93.812 124.896 ;
      RECT 0.048 125.568 93.812 125.664 ;
      RECT 0.048 126.336 93.812 126.432 ;
      RECT 0.048 127.104 93.812 127.200 ;
      RECT 0.048 127.872 93.812 127.968 ;
      RECT 0.048 128.640 93.812 128.736 ;
      RECT 0.048 129.408 93.812 129.504 ;
      RECT 0.048 130.176 93.812 130.272 ;
      RECT 0.048 130.944 93.812 131.040 ;
      RECT 0.048 131.712 93.812 131.808 ;
      RECT 0.048 132.480 93.812 132.576 ;
      RECT 0.048 133.248 93.812 133.344 ;
      RECT 0.048 134.016 93.812 134.112 ;
      RECT 0.048 134.784 93.812 134.880 ;
      RECT 0.048 135.552 93.812 135.648 ;
      RECT 0.048 136.320 93.812 136.416 ;
      RECT 0.048 137.088 93.812 137.184 ;
      RECT 0.048 137.856 93.812 137.952 ;
      RECT 0.048 138.624 93.812 138.720 ;
      RECT 0.048 139.392 93.812 139.488 ;
      RECT 0.048 140.160 93.812 140.256 ;
      RECT 0.048 140.928 93.812 141.024 ;
      RECT 0.048 141.696 93.812 141.792 ;
      RECT 0.048 142.464 93.812 142.560 ;
      RECT 0.048 143.232 93.812 143.328 ;
      RECT 0.048 144.000 93.812 144.096 ;
      RECT 0.048 144.768 93.812 144.864 ;
      RECT 0.048 145.536 93.812 145.632 ;
      RECT 0.048 146.304 93.812 146.400 ;
      RECT 0.048 147.072 93.812 147.168 ;
      RECT 0.048 147.840 93.812 147.936 ;
      RECT 0.048 148.608 93.812 148.704 ;
      RECT 0.048 149.376 93.812 149.472 ;
      RECT 0.048 150.144 93.812 150.240 ;
      RECT 0.048 150.912 93.812 151.008 ;
      RECT 0.048 151.680 93.812 151.776 ;
      RECT 0.048 152.448 93.812 152.544 ;
      RECT 0.048 153.216 93.812 153.312 ;
      RECT 0.048 153.984 93.812 154.080 ;
      RECT 0.048 154.752 93.812 154.848 ;
      RECT 0.048 155.520 93.812 155.616 ;
      RECT 0.048 156.288 93.812 156.384 ;
      RECT 0.048 157.056 93.812 157.152 ;
      RECT 0.048 157.824 93.812 157.920 ;
      RECT 0.048 158.592 93.812 158.688 ;
      RECT 0.048 159.360 93.812 159.456 ;
      RECT 0.048 160.128 93.812 160.224 ;
      RECT 0.048 160.896 93.812 160.992 ;
      RECT 0.048 161.664 93.812 161.760 ;
      RECT 0.048 162.432 93.812 162.528 ;
      RECT 0.048 163.200 93.812 163.296 ;
      RECT 0.048 163.968 93.812 164.064 ;
      RECT 0.048 164.736 93.812 164.832 ;
      RECT 0.048 165.504 93.812 165.600 ;
      RECT 0.048 166.272 93.812 166.368 ;
      RECT 0.048 167.040 93.812 167.136 ;
      RECT 0.048 167.808 93.812 167.904 ;
      RECT 0.048 168.576 93.812 168.672 ;
      RECT 0.048 169.344 93.812 169.440 ;
      RECT 0.048 170.112 93.812 170.208 ;
      RECT 0.048 170.880 93.812 170.976 ;
      RECT 0.048 171.648 93.812 171.744 ;
      RECT 0.048 172.416 93.812 172.512 ;
      RECT 0.048 173.184 93.812 173.280 ;
      RECT 0.048 173.952 93.812 174.048 ;
      RECT 0.048 174.720 93.812 174.816 ;
      RECT 0.048 175.488 93.812 175.584 ;
      RECT 0.048 176.256 93.812 176.352 ;
      RECT 0.048 177.024 93.812 177.120 ;
      RECT 0.048 177.792 93.812 177.888 ;
      RECT 0.048 178.560 93.812 178.656 ;
      RECT 0.048 179.328 93.812 179.424 ;
      RECT 0.048 180.096 93.812 180.192 ;
      RECT 0.048 180.864 93.812 180.960 ;
      RECT 0.048 181.632 93.812 181.728 ;
      RECT 0.048 182.400 93.812 182.496 ;
      RECT 0.048 183.168 93.812 183.264 ;
      RECT 0.048 183.936 93.812 184.032 ;
      RECT 0.048 184.704 93.812 184.800 ;
      RECT 0.048 185.472 93.812 185.568 ;
      RECT 0.048 186.240 93.812 186.336 ;
      RECT 0.048 187.008 93.812 187.104 ;
      RECT 0.048 187.776 93.812 187.872 ;
      RECT 0.048 188.544 93.812 188.640 ;
      RECT 0.048 189.312 93.812 189.408 ;
      RECT 0.048 190.080 93.812 190.176 ;
      RECT 0.048 190.848 93.812 190.944 ;
      RECT 0.048 191.616 93.812 191.712 ;
      RECT 0.048 192.384 93.812 192.480 ;
      RECT 0.048 193.152 93.812 193.248 ;
      RECT 0.048 193.920 93.812 194.016 ;
      RECT 0.048 194.688 93.812 194.784 ;
      RECT 0.048 195.456 93.812 195.552 ;
      RECT 0.048 196.224 93.812 196.320 ;
      RECT 0.048 196.992 93.812 197.088 ;
      RECT 0.048 197.760 93.812 197.856 ;
      RECT 0.048 198.528 93.812 198.624 ;
      RECT 0.048 199.296 93.812 199.392 ;
      RECT 0.048 200.064 93.812 200.160 ;
      RECT 0.048 200.832 93.812 200.928 ;
      RECT 0.048 201.600 93.812 201.696 ;
      RECT 0.048 202.368 93.812 202.464 ;
      RECT 0.048 203.136 93.812 203.232 ;
      RECT 0.048 203.904 93.812 204.000 ;
      RECT 0.048 204.672 93.812 204.768 ;
      RECT 0.048 205.440 93.812 205.536 ;
      RECT 0.048 206.208 93.812 206.304 ;
      RECT 0.048 206.976 93.812 207.072 ;
      RECT 0.048 207.744 93.812 207.840 ;
      RECT 0.048 208.512 93.812 208.608 ;
      RECT 0.048 209.280 93.812 209.376 ;
      RECT 0.048 210.048 93.812 210.144 ;
      RECT 0.048 210.816 93.812 210.912 ;
      RECT 0.048 211.584 93.812 211.680 ;
      RECT 0.048 212.352 93.812 212.448 ;
      RECT 0.048 213.120 93.812 213.216 ;
      RECT 0.048 213.888 93.812 213.984 ;
      RECT 0.048 214.656 93.812 214.752 ;
      RECT 0.048 215.424 93.812 215.520 ;
      RECT 0.048 216.192 93.812 216.288 ;
      RECT 0.048 216.960 93.812 217.056 ;
      RECT 0.048 217.728 93.812 217.824 ;
      RECT 0.048 218.496 93.812 218.592 ;
      RECT 0.048 219.264 93.812 219.360 ;
      RECT 0.048 220.032 93.812 220.128 ;
      RECT 0.048 220.800 93.812 220.896 ;
      RECT 0.048 221.568 93.812 221.664 ;
      RECT 0.048 222.336 93.812 222.432 ;
      RECT 0.048 223.104 93.812 223.200 ;
      RECT 0.048 223.872 93.812 223.968 ;
      RECT 0.048 224.640 93.812 224.736 ;
      RECT 0.048 225.408 93.812 225.504 ;
      RECT 0.048 226.176 93.812 226.272 ;
      RECT 0.048 226.944 93.812 227.040 ;
      RECT 0.048 227.712 93.812 227.808 ;
      RECT 0.048 228.480 93.812 228.576 ;
      RECT 0.048 229.248 93.812 229.344 ;
      RECT 0.048 230.016 93.812 230.112 ;
      RECT 0.048 230.784 93.812 230.880 ;
      RECT 0.048 231.552 93.812 231.648 ;
      RECT 0.048 232.320 93.812 232.416 ;
      RECT 0.048 233.088 93.812 233.184 ;
      RECT 0.048 233.856 93.812 233.952 ;
      RECT 0.048 234.624 93.812 234.720 ;
      RECT 0.048 235.392 93.812 235.488 ;
      RECT 0.048 236.160 93.812 236.256 ;
      RECT 0.048 236.928 93.812 237.024 ;
      RECT 0.048 237.696 93.812 237.792 ;
      RECT 0.048 238.464 93.812 238.560 ;
      RECT 0.048 239.232 93.812 239.328 ;
      RECT 0.048 240.000 93.812 240.096 ;
      RECT 0.048 240.768 93.812 240.864 ;
      RECT 0.048 241.536 93.812 241.632 ;
      RECT 0.048 242.304 93.812 242.400 ;
      RECT 0.048 243.072 93.812 243.168 ;
      RECT 0.048 243.840 93.812 243.936 ;
      RECT 0.048 244.608 93.812 244.704 ;
      RECT 0.048 245.376 93.812 245.472 ;
      RECT 0.048 246.144 93.812 246.240 ;
      RECT 0.048 246.912 93.812 247.008 ;
      RECT 0.048 247.680 93.812 247.776 ;
      RECT 0.048 248.448 93.812 248.544 ;
      RECT 0.048 249.216 93.812 249.312 ;
      RECT 0.048 249.984 93.812 250.080 ;
      RECT 0.048 250.752 93.812 250.848 ;
      RECT 0.048 251.520 93.812 251.616 ;
      RECT 0.048 252.288 93.812 252.384 ;
      RECT 0.048 253.056 93.812 253.152 ;
      RECT 0.048 253.824 93.812 253.920 ;
      RECT 0.048 254.592 93.812 254.688 ;
      RECT 0.048 255.360 93.812 255.456 ;
      RECT 0.048 256.128 93.812 256.224 ;
      RECT 0.048 256.896 93.812 256.992 ;
      RECT 0.048 257.664 93.812 257.760 ;
      RECT 0.048 258.432 93.812 258.528 ;
      RECT 0.048 259.200 93.812 259.296 ;
      RECT 0.048 259.968 93.812 260.064 ;
      RECT 0.048 260.736 93.812 260.832 ;
      RECT 0.048 261.504 93.812 261.600 ;
      RECT 0.048 262.272 93.812 262.368 ;
      RECT 0.048 263.040 93.812 263.136 ;
      RECT 0.048 263.808 93.812 263.904 ;
      RECT 0.048 264.576 93.812 264.672 ;
      RECT 0.048 265.344 93.812 265.440 ;
      RECT 0.048 266.112 93.812 266.208 ;
      RECT 0.048 266.880 93.812 266.976 ;
      RECT 0.048 267.648 93.812 267.744 ;
      RECT 0.048 268.416 93.812 268.512 ;
      RECT 0.048 269.184 93.812 269.280 ;
      RECT 0.048 269.952 93.812 270.048 ;
      RECT 0.048 270.720 93.812 270.816 ;
      RECT 0.048 271.488 93.812 271.584 ;
      RECT 0.048 272.256 93.812 272.352 ;
      RECT 0.048 273.024 93.812 273.120 ;
      RECT 0.048 273.792 93.812 273.888 ;
      RECT 0.048 274.560 93.812 274.656 ;
      RECT 0.048 275.328 93.812 275.424 ;
      RECT 0.048 276.096 93.812 276.192 ;
      RECT 0.048 276.864 93.812 276.960 ;
      RECT 0.048 277.632 93.812 277.728 ;
      RECT 0.048 278.400 93.812 278.496 ;
      RECT 0.048 279.168 93.812 279.264 ;
      RECT 0.048 279.936 93.812 280.032 ;
      RECT 0.048 280.704 93.812 280.800 ;
      RECT 0.048 281.472 93.812 281.568 ;
      RECT 0.048 282.240 93.812 282.336 ;
      RECT 0.048 283.008 93.812 283.104 ;
      RECT 0.048 283.776 93.812 283.872 ;
      RECT 0.048 284.544 93.812 284.640 ;
      RECT 0.048 285.312 93.812 285.408 ;
      RECT 0.048 286.080 93.812 286.176 ;
      RECT 0.048 286.848 93.812 286.944 ;
      RECT 0.048 287.616 93.812 287.712 ;
      RECT 0.048 288.384 93.812 288.480 ;
      RECT 0.048 289.152 93.812 289.248 ;
      RECT 0.048 289.920 93.812 290.016 ;
      RECT 0.048 290.688 93.812 290.784 ;
      RECT 0.048 291.456 93.812 291.552 ;
      RECT 0.048 292.224 93.812 292.320 ;
      RECT 0.048 292.992 93.812 293.088 ;
      RECT 0.048 293.760 93.812 293.856 ;
      RECT 0.048 294.528 93.812 294.624 ;
      RECT 0.048 295.296 93.812 295.392 ;
      RECT 0.048 296.064 93.812 296.160 ;
      RECT 0.048 296.832 93.812 296.928 ;
      RECT 0.048 297.600 93.812 297.696 ;
      RECT 0.048 298.368 93.812 298.464 ;
      RECT 0.048 299.136 93.812 299.232 ;
      RECT 0.048 299.904 93.812 300.000 ;
      RECT 0.048 300.672 93.812 300.768 ;
      RECT 0.048 301.440 93.812 301.536 ;
      RECT 0.048 302.208 93.812 302.304 ;
      RECT 0.048 302.976 93.812 303.072 ;
      RECT 0.048 303.744 93.812 303.840 ;
      RECT 0.048 304.512 93.812 304.608 ;
      RECT 0.048 305.280 93.812 305.376 ;
      RECT 0.048 306.048 93.812 306.144 ;
      RECT 0.048 306.816 93.812 306.912 ;
      RECT 0.048 307.584 93.812 307.680 ;
      RECT 0.048 308.352 93.812 308.448 ;
      RECT 0.048 309.120 93.812 309.216 ;
      RECT 0.048 309.888 93.812 309.984 ;
      RECT 0.048 310.656 93.812 310.752 ;
      RECT 0.048 311.424 93.812 311.520 ;
      RECT 0.048 312.192 93.812 312.288 ;
      RECT 0.048 312.960 93.812 313.056 ;
      RECT 0.048 313.728 93.812 313.824 ;
      RECT 0.048 314.496 93.812 314.592 ;
      RECT 0.048 315.264 93.812 315.360 ;
      RECT 0.048 316.032 93.812 316.128 ;
      RECT 0.048 316.800 93.812 316.896 ;
      RECT 0.048 317.568 93.812 317.664 ;
      RECT 0.048 318.336 93.812 318.432 ;
      RECT 0.048 319.104 93.812 319.200 ;
      RECT 0.048 319.872 93.812 319.968 ;
      RECT 0.048 320.640 93.812 320.736 ;
      RECT 0.048 321.408 93.812 321.504 ;
      RECT 0.048 322.176 93.812 322.272 ;
      RECT 0.048 322.944 93.812 323.040 ;
      RECT 0.048 323.712 93.812 323.808 ;
      RECT 0.048 324.480 93.812 324.576 ;
      RECT 0.048 325.248 93.812 325.344 ;
      RECT 0.048 326.016 93.812 326.112 ;
      RECT 0.048 326.784 93.812 326.880 ;
      RECT 0.048 327.552 93.812 327.648 ;
      RECT 0.048 328.320 93.812 328.416 ;
      RECT 0.048 329.088 93.812 329.184 ;
      RECT 0.048 329.856 93.812 329.952 ;
      RECT 0.048 330.624 93.812 330.720 ;
      RECT 0.048 331.392 93.812 331.488 ;
    END
  END VDD
  OBS
    LAYER M1 ;
    RECT 0 0 93.860 331.800 ;
    LAYER M2 ;
    RECT 0 0 93.860 331.800 ;
    LAYER M3 ;
    RECT 0 0 93.860 331.800 ;
    LAYER M4 ;
    RECT 0 0 93.860 331.800 ;
  END
END fakeram7_dp_8192x64

END LIBRARY
